VERSION 5.8 ;
BUSBITCHARS "[]" ;
DIVIDERCHAR "/" ;
UNITS
    DATABASE MICRONS 1000 ;
END UNITS

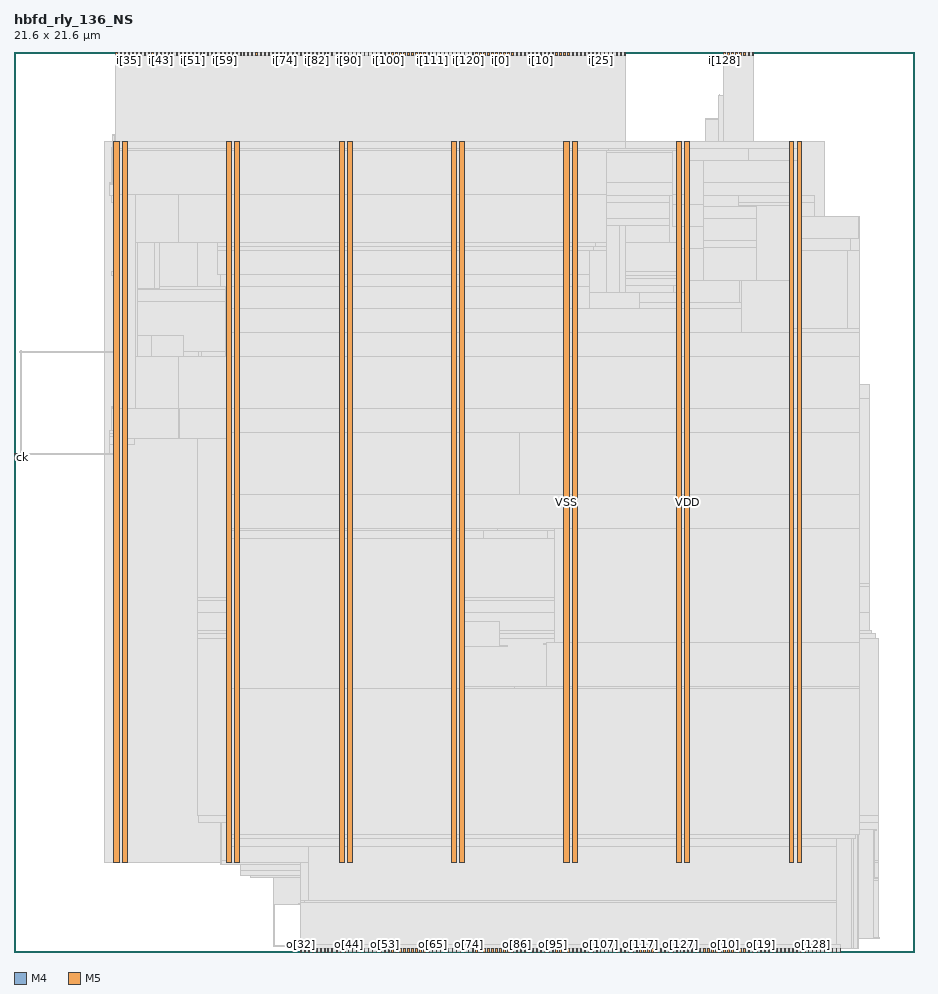
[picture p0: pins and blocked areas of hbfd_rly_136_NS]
MACRO hbfd_rly_136_NS
  FOREIGN hbfd_rly_136_NS 0 0 ;
  CLASS BLOCK ;
  SIZE 21.6 BY 21.6 ;
  PIN ck
    DIRECTION INPUT ;
    USE SIGNAL ;
    PORT
      LAYER M4 ;
        RECT  0 11.856 0.084 11.88 ;
    END
  END ck
  PIN i[0]
    DIRECTION INPUT ;
    USE SIGNAL ;
    PORT
      LAYER M5 ;
        RECT  11.664 21.516 11.688 21.6 ;
    END
  END i[0]
  PIN i[100]
    DIRECTION INPUT ;
    USE SIGNAL ;
    PORT
      LAYER M5 ;
        RECT  8.976 21.516 9 21.6 ;
    END
  END i[100]
  PIN i[101]
    DIRECTION INPUT ;
    USE SIGNAL ;
    PORT
      LAYER M5 ;
        RECT  9.072 21.516 9.096 21.6 ;
    END
  END i[101]
  PIN i[102]
    DIRECTION INPUT ;
    USE SIGNAL ;
    PORT
      LAYER M5 ;
        RECT  9.168 21.516 9.192 21.6 ;
    END
  END i[102]
  PIN i[103]
    DIRECTION INPUT ;
    USE SIGNAL ;
    PORT
      LAYER M5 ;
        RECT  9.264 21.516 9.288 21.6 ;
    END
  END i[103]
  PIN i[104]
    DIRECTION INPUT ;
    USE SIGNAL ;
    PORT
      LAYER M5 ;
        RECT  9.36 21.516 9.384 21.6 ;
    END
  END i[104]
  PIN i[105]
    DIRECTION INPUT ;
    USE SIGNAL ;
    PORT
      LAYER M5 ;
        RECT  9.456 21.516 9.48 21.6 ;
    END
  END i[105]
  PIN i[106]
    DIRECTION INPUT ;
    USE SIGNAL ;
    PORT
      LAYER M5 ;
        RECT  9.552 21.516 9.576 21.6 ;
    END
  END i[106]
  PIN i[107]
    DIRECTION INPUT ;
    USE SIGNAL ;
    PORT
      LAYER M5 ;
        RECT  9.648 21.516 9.672 21.6 ;
    END
  END i[107]
  PIN i[108]
    DIRECTION INPUT ;
    USE SIGNAL ;
    PORT
      LAYER M5 ;
        RECT  9.744 21.516 9.768 21.6 ;
    END
  END i[108]
  PIN i[109]
    DIRECTION INPUT ;
    USE SIGNAL ;
    PORT
      LAYER M5 ;
        RECT  9.84 21.516 9.864 21.6 ;
    END
  END i[109]
  PIN i[10]
    DIRECTION INPUT ;
    USE SIGNAL ;
    PORT
      LAYER M5 ;
        RECT  12.624 21.516 12.648 21.6 ;
    END
  END i[10]
  PIN i[110]
    DIRECTION INPUT ;
    USE SIGNAL ;
    PORT
      LAYER M5 ;
        RECT  9.936 21.516 9.96 21.6 ;
    END
  END i[110]
  PIN i[111]
    DIRECTION INPUT ;
    USE SIGNAL ;
    PORT
      LAYER M5 ;
        RECT  10.032 21.516 10.056 21.6 ;
    END
  END i[111]
  PIN i[112]
    DIRECTION INPUT ;
    USE SIGNAL ;
    PORT
      LAYER M5 ;
        RECT  10.128 21.516 10.152 21.6 ;
    END
  END i[112]
  PIN i[113]
    DIRECTION INPUT ;
    USE SIGNAL ;
    PORT
      LAYER M5 ;
        RECT  10.224 21.516 10.248 21.6 ;
    END
  END i[113]
  PIN i[114]
    DIRECTION INPUT ;
    USE SIGNAL ;
    PORT
      LAYER M5 ;
        RECT  10.32 21.516 10.344 21.6 ;
    END
  END i[114]
  PIN i[115]
    DIRECTION INPUT ;
    USE SIGNAL ;
    PORT
      LAYER M5 ;
        RECT  10.416 21.516 10.44 21.6 ;
    END
  END i[115]
  PIN i[116]
    DIRECTION INPUT ;
    USE SIGNAL ;
    PORT
      LAYER M5 ;
        RECT  10.512 21.516 10.536 21.6 ;
    END
  END i[116]
  PIN i[117]
    DIRECTION INPUT ;
    USE SIGNAL ;
    PORT
      LAYER M5 ;
        RECT  10.608 21.516 10.632 21.6 ;
    END
  END i[117]
  PIN i[118]
    DIRECTION INPUT ;
    USE SIGNAL ;
    PORT
      LAYER M5 ;
        RECT  10.704 21.516 10.728 21.6 ;
    END
  END i[118]
  PIN i[119]
    DIRECTION INPUT ;
    USE SIGNAL ;
    PORT
      LAYER M5 ;
        RECT  10.8 21.516 10.824 21.6 ;
    END
  END i[119]
  PIN i[11]
    DIRECTION INPUT ;
    USE SIGNAL ;
    PORT
      LAYER M5 ;
        RECT  12.72 21.516 12.744 21.6 ;
    END
  END i[11]
  PIN i[120]
    DIRECTION INPUT ;
    USE SIGNAL ;
    PORT
      LAYER M5 ;
        RECT  10.896 21.516 10.92 21.6 ;
    END
  END i[120]
  PIN i[121]
    DIRECTION INPUT ;
    USE SIGNAL ;
    PORT
      LAYER M5 ;
        RECT  10.992 21.516 11.016 21.6 ;
    END
  END i[121]
  PIN i[122]
    DIRECTION INPUT ;
    USE SIGNAL ;
    PORT
      LAYER M5 ;
        RECT  11.088 21.516 11.112 21.6 ;
    END
  END i[122]
  PIN i[123]
    DIRECTION INPUT ;
    USE SIGNAL ;
    PORT
      LAYER M5 ;
        RECT  11.184 21.516 11.208 21.6 ;
    END
  END i[123]
  PIN i[124]
    DIRECTION INPUT ;
    USE SIGNAL ;
    PORT
      LAYER M5 ;
        RECT  11.28 21.516 11.304 21.6 ;
    END
  END i[124]
  PIN i[125]
    DIRECTION INPUT ;
    USE SIGNAL ;
    PORT
      LAYER M5 ;
        RECT  11.376 21.516 11.4 21.6 ;
    END
  END i[125]
  PIN i[126]
    DIRECTION INPUT ;
    USE SIGNAL ;
    PORT
      LAYER M5 ;
        RECT  11.472 21.516 11.496 21.6 ;
    END
  END i[126]
  PIN i[127]
    DIRECTION INPUT ;
    USE SIGNAL ;
    PORT
      LAYER M5 ;
        RECT  11.568 21.516 11.592 21.6 ;
    END
  END i[127]
  PIN i[128]
    DIRECTION INPUT ;
    USE SIGNAL ;
    PORT
      LAYER M5 ;
        RECT  17.04 21.516 17.064 21.6 ;
    END
  END i[128]
  PIN i[129]
    DIRECTION INPUT ;
    USE SIGNAL ;
    PORT
      LAYER M5 ;
        RECT  17.136 21.516 17.16 21.6 ;
    END
  END i[129]
  PIN i[12]
    DIRECTION INPUT ;
    USE SIGNAL ;
    PORT
      LAYER M5 ;
        RECT  12.816 21.516 12.84 21.6 ;
    END
  END i[12]
  PIN i[130]
    DIRECTION INPUT ;
    USE SIGNAL ;
    PORT
      LAYER M5 ;
        RECT  17.232 21.516 17.256 21.6 ;
    END
  END i[130]
  PIN i[131]
    DIRECTION INPUT ;
    USE SIGNAL ;
    PORT
      LAYER M5 ;
        RECT  17.328 21.516 17.352 21.6 ;
    END
  END i[131]
  PIN i[132]
    DIRECTION INPUT ;
    USE SIGNAL ;
    PORT
      LAYER M5 ;
        RECT  17.424 21.516 17.448 21.6 ;
    END
  END i[132]
  PIN i[133]
    DIRECTION INPUT ;
    USE SIGNAL ;
    PORT
      LAYER M5 ;
        RECT  17.52 21.516 17.544 21.6 ;
    END
  END i[133]
  PIN i[134]
    DIRECTION INPUT ;
    USE SIGNAL ;
    PORT
      LAYER M5 ;
        RECT  17.616 21.516 17.64 21.6 ;
    END
  END i[134]
  PIN i[135]
    DIRECTION INPUT ;
    USE SIGNAL ;
    PORT
      LAYER M5 ;
        RECT  17.712 21.516 17.736 21.6 ;
    END
  END i[135]
  PIN i[13]
    DIRECTION INPUT ;
    USE SIGNAL ;
    PORT
      LAYER M5 ;
        RECT  12.912 21.516 12.936 21.6 ;
    END
  END i[13]
  PIN i[14]
    DIRECTION INPUT ;
    USE SIGNAL ;
    PORT
      LAYER M5 ;
        RECT  13.008 21.516 13.032 21.6 ;
    END
  END i[14]
  PIN i[15]
    DIRECTION INPUT ;
    USE SIGNAL ;
    PORT
      LAYER M5 ;
        RECT  13.104 21.516 13.128 21.6 ;
    END
  END i[15]
  PIN i[16]
    DIRECTION INPUT ;
    USE SIGNAL ;
    PORT
      LAYER M5 ;
        RECT  13.2 21.516 13.224 21.6 ;
    END
  END i[16]
  PIN i[17]
    DIRECTION INPUT ;
    USE SIGNAL ;
    PORT
      LAYER M5 ;
        RECT  13.296 21.516 13.32 21.6 ;
    END
  END i[17]
  PIN i[18]
    DIRECTION INPUT ;
    USE SIGNAL ;
    PORT
      LAYER M5 ;
        RECT  13.392 21.516 13.416 21.6 ;
    END
  END i[18]
  PIN i[19]
    DIRECTION INPUT ;
    USE SIGNAL ;
    PORT
      LAYER M5 ;
        RECT  13.488 21.516 13.512 21.6 ;
    END
  END i[19]
  PIN i[1]
    DIRECTION INPUT ;
    USE SIGNAL ;
    PORT
      LAYER M5 ;
        RECT  11.76 21.516 11.784 21.6 ;
    END
  END i[1]
  PIN i[20]
    DIRECTION INPUT ;
    USE SIGNAL ;
    PORT
      LAYER M5 ;
        RECT  13.584 21.516 13.608 21.6 ;
    END
  END i[20]
  PIN i[21]
    DIRECTION INPUT ;
    USE SIGNAL ;
    PORT
      LAYER M5 ;
        RECT  13.68 21.516 13.704 21.6 ;
    END
  END i[21]
  PIN i[22]
    DIRECTION INPUT ;
    USE SIGNAL ;
    PORT
      LAYER M5 ;
        RECT  13.776 21.516 13.8 21.6 ;
    END
  END i[22]
  PIN i[23]
    DIRECTION INPUT ;
    USE SIGNAL ;
    PORT
      LAYER M5 ;
        RECT  13.872 21.516 13.896 21.6 ;
    END
  END i[23]
  PIN i[24]
    DIRECTION INPUT ;
    USE SIGNAL ;
    PORT
      LAYER M5 ;
        RECT  13.968 21.516 13.992 21.6 ;
    END
  END i[24]
  PIN i[25]
    DIRECTION INPUT ;
    USE SIGNAL ;
    PORT
      LAYER M5 ;
        RECT  14.064 21.516 14.088 21.6 ;
    END
  END i[25]
  PIN i[26]
    DIRECTION INPUT ;
    USE SIGNAL ;
    PORT
      LAYER M5 ;
        RECT  14.16 21.516 14.184 21.6 ;
    END
  END i[26]
  PIN i[27]
    DIRECTION INPUT ;
    USE SIGNAL ;
    PORT
      LAYER M5 ;
        RECT  14.256 21.516 14.28 21.6 ;
    END
  END i[27]
  PIN i[28]
    DIRECTION INPUT ;
    USE SIGNAL ;
    PORT
      LAYER M5 ;
        RECT  14.352 21.516 14.376 21.6 ;
    END
  END i[28]
  PIN i[29]
    DIRECTION INPUT ;
    USE SIGNAL ;
    PORT
      LAYER M5 ;
        RECT  14.448 21.516 14.472 21.6 ;
    END
  END i[29]
  PIN i[2]
    DIRECTION INPUT ;
    USE SIGNAL ;
    PORT
      LAYER M5 ;
        RECT  11.856 21.516 11.88 21.6 ;
    END
  END i[2]
  PIN i[30]
    DIRECTION INPUT ;
    USE SIGNAL ;
    PORT
      LAYER M5 ;
        RECT  14.544 21.516 14.568 21.6 ;
    END
  END i[30]
  PIN i[31]
    DIRECTION INPUT ;
    USE SIGNAL ;
    PORT
      LAYER M5 ;
        RECT  14.64 21.516 14.664 21.6 ;
    END
  END i[31]
  PIN i[32]
    DIRECTION INPUT ;
    USE SIGNAL ;
    PORT
      LAYER M5 ;
        RECT  2.448 21.516 2.472 21.6 ;
    END
  END i[32]
  PIN i[33]
    DIRECTION INPUT ;
    USE SIGNAL ;
    PORT
      LAYER M5 ;
        RECT  2.544 21.516 2.568 21.6 ;
    END
  END i[33]
  PIN i[34]
    DIRECTION INPUT ;
    USE SIGNAL ;
    PORT
      LAYER M5 ;
        RECT  2.64 21.516 2.664 21.6 ;
    END
  END i[34]
  PIN i[35]
    DIRECTION INPUT ;
    USE SIGNAL ;
    PORT
      LAYER M5 ;
        RECT  2.736 21.516 2.76 21.6 ;
    END
  END i[35]
  PIN i[36]
    DIRECTION INPUT ;
    USE SIGNAL ;
    PORT
      LAYER M5 ;
        RECT  2.832 21.516 2.856 21.6 ;
    END
  END i[36]
  PIN i[37]
    DIRECTION INPUT ;
    USE SIGNAL ;
    PORT
      LAYER M5 ;
        RECT  2.928 21.516 2.952 21.6 ;
    END
  END i[37]
  PIN i[38]
    DIRECTION INPUT ;
    USE SIGNAL ;
    PORT
      LAYER M5 ;
        RECT  3.024 21.516 3.048 21.6 ;
    END
  END i[38]
  PIN i[39]
    DIRECTION INPUT ;
    USE SIGNAL ;
    PORT
      LAYER M5 ;
        RECT  3.12 21.516 3.144 21.6 ;
    END
  END i[39]
  PIN i[3]
    DIRECTION INPUT ;
    USE SIGNAL ;
    PORT
      LAYER M5 ;
        RECT  11.952 21.516 11.976 21.6 ;
    END
  END i[3]
  PIN i[40]
    DIRECTION INPUT ;
    USE SIGNAL ;
    PORT
      LAYER M5 ;
        RECT  3.216 21.516 3.24 21.6 ;
    END
  END i[40]
  PIN i[41]
    DIRECTION INPUT ;
    USE SIGNAL ;
    PORT
      LAYER M5 ;
        RECT  3.312 21.516 3.336 21.6 ;
    END
  END i[41]
  PIN i[42]
    DIRECTION INPUT ;
    USE SIGNAL ;
    PORT
      LAYER M5 ;
        RECT  3.408 21.516 3.432 21.6 ;
    END
  END i[42]
  PIN i[43]
    DIRECTION INPUT ;
    USE SIGNAL ;
    PORT
      LAYER M5 ;
        RECT  3.504 21.516 3.528 21.6 ;
    END
  END i[43]
  PIN i[44]
    DIRECTION INPUT ;
    USE SIGNAL ;
    PORT
      LAYER M5 ;
        RECT  3.6 21.516 3.624 21.6 ;
    END
  END i[44]
  PIN i[45]
    DIRECTION INPUT ;
    USE SIGNAL ;
    PORT
      LAYER M5 ;
        RECT  3.696 21.516 3.72 21.6 ;
    END
  END i[45]
  PIN i[46]
    DIRECTION INPUT ;
    USE SIGNAL ;
    PORT
      LAYER M5 ;
        RECT  3.792 21.516 3.816 21.6 ;
    END
  END i[46]
  PIN i[47]
    DIRECTION INPUT ;
    USE SIGNAL ;
    PORT
      LAYER M5 ;
        RECT  3.888 21.516 3.912 21.6 ;
    END
  END i[47]
  PIN i[48]
    DIRECTION INPUT ;
    USE SIGNAL ;
    PORT
      LAYER M5 ;
        RECT  3.984 21.516 4.008 21.6 ;
    END
  END i[48]
  PIN i[49]
    DIRECTION INPUT ;
    USE SIGNAL ;
    PORT
      LAYER M5 ;
        RECT  4.08 21.516 4.104 21.6 ;
    END
  END i[49]
  PIN i[4]
    DIRECTION INPUT ;
    USE SIGNAL ;
    PORT
      LAYER M5 ;
        RECT  12.048 21.516 12.072 21.6 ;
    END
  END i[4]
  PIN i[50]
    DIRECTION INPUT ;
    USE SIGNAL ;
    PORT
      LAYER M5 ;
        RECT  4.176 21.516 4.2 21.6 ;
    END
  END i[50]
  PIN i[51]
    DIRECTION INPUT ;
    USE SIGNAL ;
    PORT
      LAYER M5 ;
        RECT  4.272 21.516 4.296 21.6 ;
    END
  END i[51]
  PIN i[52]
    DIRECTION INPUT ;
    USE SIGNAL ;
    PORT
      LAYER M5 ;
        RECT  4.368 21.516 4.392 21.6 ;
    END
  END i[52]
  PIN i[53]
    DIRECTION INPUT ;
    USE SIGNAL ;
    PORT
      LAYER M5 ;
        RECT  4.464 21.516 4.488 21.6 ;
    END
  END i[53]
  PIN i[54]
    DIRECTION INPUT ;
    USE SIGNAL ;
    PORT
      LAYER M5 ;
        RECT  4.56 21.516 4.584 21.6 ;
    END
  END i[54]
  PIN i[55]
    DIRECTION INPUT ;
    USE SIGNAL ;
    PORT
      LAYER M5 ;
        RECT  4.656 21.516 4.68 21.6 ;
    END
  END i[55]
  PIN i[56]
    DIRECTION INPUT ;
    USE SIGNAL ;
    PORT
      LAYER M5 ;
        RECT  4.752 21.516 4.776 21.6 ;
    END
  END i[56]
  PIN i[57]
    DIRECTION INPUT ;
    USE SIGNAL ;
    PORT
      LAYER M5 ;
        RECT  4.848 21.516 4.872 21.6 ;
    END
  END i[57]
  PIN i[58]
    DIRECTION INPUT ;
    USE SIGNAL ;
    PORT
      LAYER M5 ;
        RECT  4.944 21.516 4.968 21.6 ;
    END
  END i[58]
  PIN i[59]
    DIRECTION INPUT ;
    USE SIGNAL ;
    PORT
      LAYER M5 ;
        RECT  5.04 21.516 5.064 21.6 ;
    END
  END i[59]
  PIN i[5]
    DIRECTION INPUT ;
    USE SIGNAL ;
    PORT
      LAYER M5 ;
        RECT  12.144 21.516 12.168 21.6 ;
    END
  END i[5]
  PIN i[60]
    DIRECTION INPUT ;
    USE SIGNAL ;
    PORT
      LAYER M5 ;
        RECT  5.136 21.516 5.16 21.6 ;
    END
  END i[60]
  PIN i[61]
    DIRECTION INPUT ;
    USE SIGNAL ;
    PORT
      LAYER M5 ;
        RECT  5.232 21.516 5.256 21.6 ;
    END
  END i[61]
  PIN i[62]
    DIRECTION INPUT ;
    USE SIGNAL ;
    PORT
      LAYER M5 ;
        RECT  5.328 21.516 5.352 21.6 ;
    END
  END i[62]
  PIN i[63]
    DIRECTION INPUT ;
    USE SIGNAL ;
    PORT
      LAYER M5 ;
        RECT  5.424 21.516 5.448 21.6 ;
    END
  END i[63]
  PIN i[64]
    DIRECTION INPUT ;
    USE SIGNAL ;
    PORT
      LAYER M5 ;
        RECT  5.52 21.516 5.544 21.6 ;
    END
  END i[64]
  PIN i[65]
    DIRECTION INPUT ;
    USE SIGNAL ;
    PORT
      LAYER M5 ;
        RECT  5.616 21.516 5.64 21.6 ;
    END
  END i[65]
  PIN i[66]
    DIRECTION INPUT ;
    USE SIGNAL ;
    PORT
      LAYER M5 ;
        RECT  5.712 21.516 5.736 21.6 ;
    END
  END i[66]
  PIN i[67]
    DIRECTION INPUT ;
    USE SIGNAL ;
    PORT
      LAYER M5 ;
        RECT  5.808 21.516 5.832 21.6 ;
    END
  END i[67]
  PIN i[68]
    DIRECTION INPUT ;
    USE SIGNAL ;
    PORT
      LAYER M5 ;
        RECT  5.904 21.516 5.928 21.6 ;
    END
  END i[68]
  PIN i[69]
    DIRECTION INPUT ;
    USE SIGNAL ;
    PORT
      LAYER M5 ;
        RECT  6 21.516 6.024 21.6 ;
    END
  END i[69]
  PIN i[6]
    DIRECTION INPUT ;
    USE SIGNAL ;
    PORT
      LAYER M5 ;
        RECT  12.24 21.516 12.264 21.6 ;
    END
  END i[6]
  PIN i[70]
    DIRECTION INPUT ;
    USE SIGNAL ;
    PORT
      LAYER M5 ;
        RECT  6.096 21.516 6.12 21.6 ;
    END
  END i[70]
  PIN i[71]
    DIRECTION INPUT ;
    USE SIGNAL ;
    PORT
      LAYER M5 ;
        RECT  6.192 21.516 6.216 21.6 ;
    END
  END i[71]
  PIN i[72]
    DIRECTION INPUT ;
    USE SIGNAL ;
    PORT
      LAYER M5 ;
        RECT  6.288 21.516 6.312 21.6 ;
    END
  END i[72]
  PIN i[73]
    DIRECTION INPUT ;
    USE SIGNAL ;
    PORT
      LAYER M5 ;
        RECT  6.384 21.516 6.408 21.6 ;
    END
  END i[73]
  PIN i[74]
    DIRECTION INPUT ;
    USE SIGNAL ;
    PORT
      LAYER M5 ;
        RECT  6.48 21.516 6.504 21.6 ;
    END
  END i[74]
  PIN i[75]
    DIRECTION INPUT ;
    USE SIGNAL ;
    PORT
      LAYER M5 ;
        RECT  6.576 21.516 6.6 21.6 ;
    END
  END i[75]
  PIN i[76]
    DIRECTION INPUT ;
    USE SIGNAL ;
    PORT
      LAYER M5 ;
        RECT  6.672 21.516 6.696 21.6 ;
    END
  END i[76]
  PIN i[77]
    DIRECTION INPUT ;
    USE SIGNAL ;
    PORT
      LAYER M5 ;
        RECT  6.768 21.516 6.792 21.6 ;
    END
  END i[77]
  PIN i[78]
    DIRECTION INPUT ;
    USE SIGNAL ;
    PORT
      LAYER M5 ;
        RECT  6.864 21.516 6.888 21.6 ;
    END
  END i[78]
  PIN i[79]
    DIRECTION INPUT ;
    USE SIGNAL ;
    PORT
      LAYER M5 ;
        RECT  6.96 21.516 6.984 21.6 ;
    END
  END i[79]
  PIN i[7]
    DIRECTION INPUT ;
    USE SIGNAL ;
    PORT
      LAYER M5 ;
        RECT  12.336 21.516 12.36 21.6 ;
    END
  END i[7]
  PIN i[80]
    DIRECTION INPUT ;
    USE SIGNAL ;
    PORT
      LAYER M5 ;
        RECT  7.056 21.516 7.08 21.6 ;
    END
  END i[80]
  PIN i[81]
    DIRECTION INPUT ;
    USE SIGNAL ;
    PORT
      LAYER M5 ;
        RECT  7.152 21.516 7.176 21.6 ;
    END
  END i[81]
  PIN i[82]
    DIRECTION INPUT ;
    USE SIGNAL ;
    PORT
      LAYER M5 ;
        RECT  7.248 21.516 7.272 21.6 ;
    END
  END i[82]
  PIN i[83]
    DIRECTION INPUT ;
    USE SIGNAL ;
    PORT
      LAYER M5 ;
        RECT  7.344 21.516 7.368 21.6 ;
    END
  END i[83]
  PIN i[84]
    DIRECTION INPUT ;
    USE SIGNAL ;
    PORT
      LAYER M5 ;
        RECT  7.44 21.516 7.464 21.6 ;
    END
  END i[84]
  PIN i[85]
    DIRECTION INPUT ;
    USE SIGNAL ;
    PORT
      LAYER M5 ;
        RECT  7.536 21.516 7.56 21.6 ;
    END
  END i[85]
  PIN i[86]
    DIRECTION INPUT ;
    USE SIGNAL ;
    PORT
      LAYER M5 ;
        RECT  7.632 21.516 7.656 21.6 ;
    END
  END i[86]
  PIN i[87]
    DIRECTION INPUT ;
    USE SIGNAL ;
    PORT
      LAYER M5 ;
        RECT  7.728 21.516 7.752 21.6 ;
    END
  END i[87]
  PIN i[88]
    DIRECTION INPUT ;
    USE SIGNAL ;
    PORT
      LAYER M5 ;
        RECT  7.824 21.516 7.848 21.6 ;
    END
  END i[88]
  PIN i[89]
    DIRECTION INPUT ;
    USE SIGNAL ;
    PORT
      LAYER M5 ;
        RECT  7.92 21.516 7.944 21.6 ;
    END
  END i[89]
  PIN i[8]
    DIRECTION INPUT ;
    USE SIGNAL ;
    PORT
      LAYER M5 ;
        RECT  12.432 21.516 12.456 21.6 ;
    END
  END i[8]
  PIN i[90]
    DIRECTION INPUT ;
    USE SIGNAL ;
    PORT
      LAYER M5 ;
        RECT  8.016 21.516 8.04 21.6 ;
    END
  END i[90]
  PIN i[91]
    DIRECTION INPUT ;
    USE SIGNAL ;
    PORT
      LAYER M5 ;
        RECT  8.112 21.516 8.136 21.6 ;
    END
  END i[91]
  PIN i[92]
    DIRECTION INPUT ;
    USE SIGNAL ;
    PORT
      LAYER M5 ;
        RECT  8.208 21.516 8.232 21.6 ;
    END
  END i[92]
  PIN i[93]
    DIRECTION INPUT ;
    USE SIGNAL ;
    PORT
      LAYER M5 ;
        RECT  8.304 21.516 8.328 21.6 ;
    END
  END i[93]
  PIN i[94]
    DIRECTION INPUT ;
    USE SIGNAL ;
    PORT
      LAYER M5 ;
        RECT  8.4 21.516 8.424 21.6 ;
    END
  END i[94]
  PIN i[95]
    DIRECTION INPUT ;
    USE SIGNAL ;
    PORT
      LAYER M5 ;
        RECT  8.496 21.516 8.52 21.6 ;
    END
  END i[95]
  PIN i[96]
    DIRECTION INPUT ;
    USE SIGNAL ;
    PORT
      LAYER M5 ;
        RECT  8.592 21.516 8.616 21.6 ;
    END
  END i[96]
  PIN i[97]
    DIRECTION INPUT ;
    USE SIGNAL ;
    PORT
      LAYER M5 ;
        RECT  8.688 21.516 8.712 21.6 ;
    END
  END i[97]
  PIN i[98]
    DIRECTION INPUT ;
    USE SIGNAL ;
    PORT
      LAYER M5 ;
        RECT  8.784 21.516 8.808 21.6 ;
    END
  END i[98]
  PIN i[99]
    DIRECTION INPUT ;
    USE SIGNAL ;
    PORT
      LAYER M5 ;
        RECT  8.88 21.516 8.904 21.6 ;
    END
  END i[99]
  PIN i[9]
    DIRECTION INPUT ;
    USE SIGNAL ;
    PORT
      LAYER M5 ;
        RECT  12.528 21.516 12.552 21.6 ;
    END
  END i[9]
  PIN o[0]
    DIRECTION OUTPUT ;
    USE SIGNAL ;
    PORT
      LAYER M5 ;
        RECT  16.08 0 16.104 0.084 ;
    END
  END o[0]
  PIN o[100]
    DIRECTION OUTPUT ;
    USE SIGNAL ;
    PORT
      LAYER M5 ;
        RECT  13.392 0 13.416 0.084 ;
    END
  END o[100]
  PIN o[101]
    DIRECTION OUTPUT ;
    USE SIGNAL ;
    PORT
      LAYER M5 ;
        RECT  13.488 0 13.512 0.084 ;
    END
  END o[101]
  PIN o[102]
    DIRECTION OUTPUT ;
    USE SIGNAL ;
    PORT
      LAYER M5 ;
        RECT  13.584 0 13.608 0.084 ;
    END
  END o[102]
  PIN o[103]
    DIRECTION OUTPUT ;
    USE SIGNAL ;
    PORT
      LAYER M5 ;
        RECT  13.68 0 13.704 0.084 ;
    END
  END o[103]
  PIN o[104]
    DIRECTION OUTPUT ;
    USE SIGNAL ;
    PORT
      LAYER M5 ;
        RECT  13.776 0 13.8 0.084 ;
    END
  END o[104]
  PIN o[105]
    DIRECTION OUTPUT ;
    USE SIGNAL ;
    PORT
      LAYER M5 ;
        RECT  13.872 0 13.896 0.084 ;
    END
  END o[105]
  PIN o[106]
    DIRECTION OUTPUT ;
    USE SIGNAL ;
    PORT
      LAYER M5 ;
        RECT  13.968 0 13.992 0.084 ;
    END
  END o[106]
  PIN o[107]
    DIRECTION OUTPUT ;
    USE SIGNAL ;
    PORT
      LAYER M5 ;
        RECT  14.064 0 14.088 0.084 ;
    END
  END o[107]
  PIN o[108]
    DIRECTION OUTPUT ;
    USE SIGNAL ;
    PORT
      LAYER M5 ;
        RECT  14.16 0 14.184 0.084 ;
    END
  END o[108]
  PIN o[109]
    DIRECTION OUTPUT ;
    USE SIGNAL ;
    PORT
      LAYER M5 ;
        RECT  14.256 0 14.28 0.084 ;
    END
  END o[109]
  PIN o[10]
    DIRECTION OUTPUT ;
    USE SIGNAL ;
    PORT
      LAYER M5 ;
        RECT  17.04 0 17.064 0.084 ;
    END
  END o[10]
  PIN o[110]
    DIRECTION OUTPUT ;
    USE SIGNAL ;
    PORT
      LAYER M5 ;
        RECT  14.352 0 14.376 0.084 ;
    END
  END o[110]
  PIN o[111]
    DIRECTION OUTPUT ;
    USE SIGNAL ;
    PORT
      LAYER M5 ;
        RECT  14.448 0 14.472 0.084 ;
    END
  END o[111]
  PIN o[112]
    DIRECTION OUTPUT ;
    USE SIGNAL ;
    PORT
      LAYER M5 ;
        RECT  14.544 0 14.568 0.084 ;
    END
  END o[112]
  PIN o[113]
    DIRECTION OUTPUT ;
    USE SIGNAL ;
    PORT
      LAYER M5 ;
        RECT  14.64 0 14.664 0.084 ;
    END
  END o[113]
  PIN o[114]
    DIRECTION OUTPUT ;
    USE SIGNAL ;
    PORT
      LAYER M5 ;
        RECT  14.736 0 14.76 0.084 ;
    END
  END o[114]
  PIN o[115]
    DIRECTION OUTPUT ;
    USE SIGNAL ;
    PORT
      LAYER M5 ;
        RECT  14.832 0 14.856 0.084 ;
    END
  END o[115]
  PIN o[116]
    DIRECTION OUTPUT ;
    USE SIGNAL ;
    PORT
      LAYER M5 ;
        RECT  14.928 0 14.952 0.084 ;
    END
  END o[116]
  PIN o[117]
    DIRECTION OUTPUT ;
    USE SIGNAL ;
    PORT
      LAYER M5 ;
        RECT  15.024 0 15.048 0.084 ;
    END
  END o[117]
  PIN o[118]
    DIRECTION OUTPUT ;
    USE SIGNAL ;
    PORT
      LAYER M5 ;
        RECT  15.12 0 15.144 0.084 ;
    END
  END o[118]
  PIN o[119]
    DIRECTION OUTPUT ;
    USE SIGNAL ;
    PORT
      LAYER M5 ;
        RECT  15.216 0 15.24 0.084 ;
    END
  END o[119]
  PIN o[11]
    DIRECTION OUTPUT ;
    USE SIGNAL ;
    PORT
      LAYER M5 ;
        RECT  17.136 0 17.16 0.084 ;
    END
  END o[11]
  PIN o[120]
    DIRECTION OUTPUT ;
    USE SIGNAL ;
    PORT
      LAYER M5 ;
        RECT  15.312 0 15.336 0.084 ;
    END
  END o[120]
  PIN o[121]
    DIRECTION OUTPUT ;
    USE SIGNAL ;
    PORT
      LAYER M5 ;
        RECT  15.408 0 15.432 0.084 ;
    END
  END o[121]
  PIN o[122]
    DIRECTION OUTPUT ;
    USE SIGNAL ;
    PORT
      LAYER M5 ;
        RECT  15.504 0 15.528 0.084 ;
    END
  END o[122]
  PIN o[123]
    DIRECTION OUTPUT ;
    USE SIGNAL ;
    PORT
      LAYER M5 ;
        RECT  15.6 0 15.624 0.084 ;
    END
  END o[123]
  PIN o[124]
    DIRECTION OUTPUT ;
    USE SIGNAL ;
    PORT
      LAYER M5 ;
        RECT  15.696 0 15.72 0.084 ;
    END
  END o[124]
  PIN o[125]
    DIRECTION OUTPUT ;
    USE SIGNAL ;
    PORT
      LAYER M5 ;
        RECT  15.792 0 15.816 0.084 ;
    END
  END o[125]
  PIN o[126]
    DIRECTION OUTPUT ;
    USE SIGNAL ;
    PORT
      LAYER M5 ;
        RECT  15.888 0 15.912 0.084 ;
    END
  END o[126]
  PIN o[127]
    DIRECTION OUTPUT ;
    USE SIGNAL ;
    PORT
      LAYER M5 ;
        RECT  15.984 0 16.008 0.084 ;
    END
  END o[127]
  PIN o[128]
    DIRECTION OUTPUT ;
    USE SIGNAL ;
    PORT
      LAYER M5 ;
        RECT  19.152 0 19.176 0.084 ;
    END
  END o[128]
  PIN o[129]
    DIRECTION OUTPUT ;
    USE SIGNAL ;
    PORT
      LAYER M5 ;
        RECT  19.248 0 19.272 0.084 ;
    END
  END o[129]
  PIN o[12]
    DIRECTION OUTPUT ;
    USE SIGNAL ;
    PORT
      LAYER M5 ;
        RECT  17.232 0 17.256 0.084 ;
    END
  END o[12]
  PIN o[130]
    DIRECTION OUTPUT ;
    USE SIGNAL ;
    PORT
      LAYER M5 ;
        RECT  19.344 0 19.368 0.084 ;
    END
  END o[130]
  PIN o[131]
    DIRECTION OUTPUT ;
    USE SIGNAL ;
    PORT
      LAYER M5 ;
        RECT  19.44 0 19.464 0.084 ;
    END
  END o[131]
  PIN o[132]
    DIRECTION OUTPUT ;
    USE SIGNAL ;
    PORT
      LAYER M5 ;
        RECT  19.536 0 19.56 0.084 ;
    END
  END o[132]
  PIN o[133]
    DIRECTION OUTPUT ;
    USE SIGNAL ;
    PORT
      LAYER M5 ;
        RECT  19.632 0 19.656 0.084 ;
    END
  END o[133]
  PIN o[134]
    DIRECTION OUTPUT ;
    USE SIGNAL ;
    PORT
      LAYER M5 ;
        RECT  19.728 0 19.752 0.084 ;
    END
  END o[134]
  PIN o[135]
    DIRECTION OUTPUT ;
    USE SIGNAL ;
    PORT
      LAYER M5 ;
        RECT  19.824 0 19.848 0.084 ;
    END
  END o[135]
  PIN o[13]
    DIRECTION OUTPUT ;
    USE SIGNAL ;
    PORT
      LAYER M5 ;
        RECT  17.328 0 17.352 0.084 ;
    END
  END o[13]
  PIN o[14]
    DIRECTION OUTPUT ;
    USE SIGNAL ;
    PORT
      LAYER M5 ;
        RECT  17.424 0 17.448 0.084 ;
    END
  END o[14]
  PIN o[15]
    DIRECTION OUTPUT ;
    USE SIGNAL ;
    PORT
      LAYER M5 ;
        RECT  17.52 0 17.544 0.084 ;
    END
  END o[15]
  PIN o[16]
    DIRECTION OUTPUT ;
    USE SIGNAL ;
    PORT
      LAYER M5 ;
        RECT  17.616 0 17.64 0.084 ;
    END
  END o[16]
  PIN o[17]
    DIRECTION OUTPUT ;
    USE SIGNAL ;
    PORT
      LAYER M5 ;
        RECT  17.712 0 17.736 0.084 ;
    END
  END o[17]
  PIN o[18]
    DIRECTION OUTPUT ;
    USE SIGNAL ;
    PORT
      LAYER M5 ;
        RECT  17.808 0 17.832 0.084 ;
    END
  END o[18]
  PIN o[19]
    DIRECTION OUTPUT ;
    USE SIGNAL ;
    PORT
      LAYER M5 ;
        RECT  17.904 0 17.928 0.084 ;
    END
  END o[19]
  PIN o[1]
    DIRECTION OUTPUT ;
    USE SIGNAL ;
    PORT
      LAYER M5 ;
        RECT  16.176 0 16.2 0.084 ;
    END
  END o[1]
  PIN o[20]
    DIRECTION OUTPUT ;
    USE SIGNAL ;
    PORT
      LAYER M5 ;
        RECT  18 0 18.024 0.084 ;
    END
  END o[20]
  PIN o[21]
    DIRECTION OUTPUT ;
    USE SIGNAL ;
    PORT
      LAYER M5 ;
        RECT  18.096 0 18.12 0.084 ;
    END
  END o[21]
  PIN o[22]
    DIRECTION OUTPUT ;
    USE SIGNAL ;
    PORT
      LAYER M5 ;
        RECT  18.192 0 18.216 0.084 ;
    END
  END o[22]
  PIN o[23]
    DIRECTION OUTPUT ;
    USE SIGNAL ;
    PORT
      LAYER M5 ;
        RECT  18.288 0 18.312 0.084 ;
    END
  END o[23]
  PIN o[24]
    DIRECTION OUTPUT ;
    USE SIGNAL ;
    PORT
      LAYER M5 ;
        RECT  18.384 0 18.408 0.084 ;
    END
  END o[24]
  PIN o[25]
    DIRECTION OUTPUT ;
    USE SIGNAL ;
    PORT
      LAYER M5 ;
        RECT  18.48 0 18.504 0.084 ;
    END
  END o[25]
  PIN o[26]
    DIRECTION OUTPUT ;
    USE SIGNAL ;
    PORT
      LAYER M5 ;
        RECT  18.576 0 18.6 0.084 ;
    END
  END o[26]
  PIN o[27]
    DIRECTION OUTPUT ;
    USE SIGNAL ;
    PORT
      LAYER M5 ;
        RECT  18.672 0 18.696 0.084 ;
    END
  END o[27]
  PIN o[28]
    DIRECTION OUTPUT ;
    USE SIGNAL ;
    PORT
      LAYER M5 ;
        RECT  18.768 0 18.792 0.084 ;
    END
  END o[28]
  PIN o[29]
    DIRECTION OUTPUT ;
    USE SIGNAL ;
    PORT
      LAYER M5 ;
        RECT  18.864 0 18.888 0.084 ;
    END
  END o[29]
  PIN o[2]
    DIRECTION OUTPUT ;
    USE SIGNAL ;
    PORT
      LAYER M5 ;
        RECT  16.272 0 16.296 0.084 ;
    END
  END o[2]
  PIN o[30]
    DIRECTION OUTPUT ;
    USE SIGNAL ;
    PORT
      LAYER M5 ;
        RECT  18.96 0 18.984 0.084 ;
    END
  END o[30]
  PIN o[31]
    DIRECTION OUTPUT ;
    USE SIGNAL ;
    PORT
      LAYER M5 ;
        RECT  19.056 0 19.08 0.084 ;
    END
  END o[31]
  PIN o[32]
    DIRECTION OUTPUT ;
    USE SIGNAL ;
    PORT
      LAYER M5 ;
        RECT  6.864 0 6.888 0.084 ;
    END
  END o[32]
  PIN o[33]
    DIRECTION OUTPUT ;
    USE SIGNAL ;
    PORT
      LAYER M5 ;
        RECT  6.96 0 6.984 0.084 ;
    END
  END o[33]
  PIN o[34]
    DIRECTION OUTPUT ;
    USE SIGNAL ;
    PORT
      LAYER M5 ;
        RECT  7.056 0 7.08 0.084 ;
    END
  END o[34]
  PIN o[35]
    DIRECTION OUTPUT ;
    USE SIGNAL ;
    PORT
      LAYER M5 ;
        RECT  7.152 0 7.176 0.084 ;
    END
  END o[35]
  PIN o[36]
    DIRECTION OUTPUT ;
    USE SIGNAL ;
    PORT
      LAYER M5 ;
        RECT  7.248 0 7.272 0.084 ;
    END
  END o[36]
  PIN o[37]
    DIRECTION OUTPUT ;
    USE SIGNAL ;
    PORT
      LAYER M5 ;
        RECT  7.344 0 7.368 0.084 ;
    END
  END o[37]
  PIN o[38]
    DIRECTION OUTPUT ;
    USE SIGNAL ;
    PORT
      LAYER M5 ;
        RECT  7.44 0 7.464 0.084 ;
    END
  END o[38]
  PIN o[39]
    DIRECTION OUTPUT ;
    USE SIGNAL ;
    PORT
      LAYER M5 ;
        RECT  7.536 0 7.56 0.084 ;
    END
  END o[39]
  PIN o[3]
    DIRECTION OUTPUT ;
    USE SIGNAL ;
    PORT
      LAYER M5 ;
        RECT  16.368 0 16.392 0.084 ;
    END
  END o[3]
  PIN o[40]
    DIRECTION OUTPUT ;
    USE SIGNAL ;
    PORT
      LAYER M5 ;
        RECT  7.632 0 7.656 0.084 ;
    END
  END o[40]
  PIN o[41]
    DIRECTION OUTPUT ;
    USE SIGNAL ;
    PORT
      LAYER M5 ;
        RECT  7.728 0 7.752 0.084 ;
    END
  END o[41]
  PIN o[42]
    DIRECTION OUTPUT ;
    USE SIGNAL ;
    PORT
      LAYER M5 ;
        RECT  7.824 0 7.848 0.084 ;
    END
  END o[42]
  PIN o[43]
    DIRECTION OUTPUT ;
    USE SIGNAL ;
    PORT
      LAYER M5 ;
        RECT  7.92 0 7.944 0.084 ;
    END
  END o[43]
  PIN o[44]
    DIRECTION OUTPUT ;
    USE SIGNAL ;
    PORT
      LAYER M5 ;
        RECT  8.016 0 8.04 0.084 ;
    END
  END o[44]
  PIN o[45]
    DIRECTION OUTPUT ;
    USE SIGNAL ;
    PORT
      LAYER M5 ;
        RECT  8.112 0 8.136 0.084 ;
    END
  END o[45]
  PIN o[46]
    DIRECTION OUTPUT ;
    USE SIGNAL ;
    PORT
      LAYER M5 ;
        RECT  8.208 0 8.232 0.084 ;
    END
  END o[46]
  PIN o[47]
    DIRECTION OUTPUT ;
    USE SIGNAL ;
    PORT
      LAYER M5 ;
        RECT  8.304 0 8.328 0.084 ;
    END
  END o[47]
  PIN o[48]
    DIRECTION OUTPUT ;
    USE SIGNAL ;
    PORT
      LAYER M5 ;
        RECT  8.4 0 8.424 0.084 ;
    END
  END o[48]
  PIN o[49]
    DIRECTION OUTPUT ;
    USE SIGNAL ;
    PORT
      LAYER M5 ;
        RECT  8.496 0 8.52 0.084 ;
    END
  END o[49]
  PIN o[4]
    DIRECTION OUTPUT ;
    USE SIGNAL ;
    PORT
      LAYER M5 ;
        RECT  16.464 0 16.488 0.084 ;
    END
  END o[4]
  PIN o[50]
    DIRECTION OUTPUT ;
    USE SIGNAL ;
    PORT
      LAYER M5 ;
        RECT  8.592 0 8.616 0.084 ;
    END
  END o[50]
  PIN o[51]
    DIRECTION OUTPUT ;
    USE SIGNAL ;
    PORT
      LAYER M5 ;
        RECT  8.688 0 8.712 0.084 ;
    END
  END o[51]
  PIN o[52]
    DIRECTION OUTPUT ;
    USE SIGNAL ;
    PORT
      LAYER M5 ;
        RECT  8.784 0 8.808 0.084 ;
    END
  END o[52]
  PIN o[53]
    DIRECTION OUTPUT ;
    USE SIGNAL ;
    PORT
      LAYER M5 ;
        RECT  8.88 0 8.904 0.084 ;
    END
  END o[53]
  PIN o[54]
    DIRECTION OUTPUT ;
    USE SIGNAL ;
    PORT
      LAYER M5 ;
        RECT  8.976 0 9 0.084 ;
    END
  END o[54]
  PIN o[55]
    DIRECTION OUTPUT ;
    USE SIGNAL ;
    PORT
      LAYER M5 ;
        RECT  9.072 0 9.096 0.084 ;
    END
  END o[55]
  PIN o[56]
    DIRECTION OUTPUT ;
    USE SIGNAL ;
    PORT
      LAYER M5 ;
        RECT  9.168 0 9.192 0.084 ;
    END
  END o[56]
  PIN o[57]
    DIRECTION OUTPUT ;
    USE SIGNAL ;
    PORT
      LAYER M5 ;
        RECT  9.264 0 9.288 0.084 ;
    END
  END o[57]
  PIN o[58]
    DIRECTION OUTPUT ;
    USE SIGNAL ;
    PORT
      LAYER M5 ;
        RECT  9.36 0 9.384 0.084 ;
    END
  END o[58]
  PIN o[59]
    DIRECTION OUTPUT ;
    USE SIGNAL ;
    PORT
      LAYER M5 ;
        RECT  9.456 0 9.48 0.084 ;
    END
  END o[59]
  PIN o[5]
    DIRECTION OUTPUT ;
    USE SIGNAL ;
    PORT
      LAYER M5 ;
        RECT  16.56 0 16.584 0.084 ;
    END
  END o[5]
  PIN o[60]
    DIRECTION OUTPUT ;
    USE SIGNAL ;
    PORT
      LAYER M5 ;
        RECT  9.552 0 9.576 0.084 ;
    END
  END o[60]
  PIN o[61]
    DIRECTION OUTPUT ;
    USE SIGNAL ;
    PORT
      LAYER M5 ;
        RECT  9.648 0 9.672 0.084 ;
    END
  END o[61]
  PIN o[62]
    DIRECTION OUTPUT ;
    USE SIGNAL ;
    PORT
      LAYER M5 ;
        RECT  9.744 0 9.768 0.084 ;
    END
  END o[62]
  PIN o[63]
    DIRECTION OUTPUT ;
    USE SIGNAL ;
    PORT
      LAYER M5 ;
        RECT  9.84 0 9.864 0.084 ;
    END
  END o[63]
  PIN o[64]
    DIRECTION OUTPUT ;
    USE SIGNAL ;
    PORT
      LAYER M5 ;
        RECT  9.936 0 9.96 0.084 ;
    END
  END o[64]
  PIN o[65]
    DIRECTION OUTPUT ;
    USE SIGNAL ;
    PORT
      LAYER M5 ;
        RECT  10.032 0 10.056 0.084 ;
    END
  END o[65]
  PIN o[66]
    DIRECTION OUTPUT ;
    USE SIGNAL ;
    PORT
      LAYER M5 ;
        RECT  10.128 0 10.152 0.084 ;
    END
  END o[66]
  PIN o[67]
    DIRECTION OUTPUT ;
    USE SIGNAL ;
    PORT
      LAYER M5 ;
        RECT  10.224 0 10.248 0.084 ;
    END
  END o[67]
  PIN o[68]
    DIRECTION OUTPUT ;
    USE SIGNAL ;
    PORT
      LAYER M5 ;
        RECT  10.32 0 10.344 0.084 ;
    END
  END o[68]
  PIN o[69]
    DIRECTION OUTPUT ;
    USE SIGNAL ;
    PORT
      LAYER M5 ;
        RECT  10.416 0 10.44 0.084 ;
    END
  END o[69]
  PIN o[6]
    DIRECTION OUTPUT ;
    USE SIGNAL ;
    PORT
      LAYER M5 ;
        RECT  16.656 0 16.68 0.084 ;
    END
  END o[6]
  PIN o[70]
    DIRECTION OUTPUT ;
    USE SIGNAL ;
    PORT
      LAYER M5 ;
        RECT  10.512 0 10.536 0.084 ;
    END
  END o[70]
  PIN o[71]
    DIRECTION OUTPUT ;
    USE SIGNAL ;
    PORT
      LAYER M5 ;
        RECT  10.608 0 10.632 0.084 ;
    END
  END o[71]
  PIN o[72]
    DIRECTION OUTPUT ;
    USE SIGNAL ;
    PORT
      LAYER M5 ;
        RECT  10.704 0 10.728 0.084 ;
    END
  END o[72]
  PIN o[73]
    DIRECTION OUTPUT ;
    USE SIGNAL ;
    PORT
      LAYER M5 ;
        RECT  10.8 0 10.824 0.084 ;
    END
  END o[73]
  PIN o[74]
    DIRECTION OUTPUT ;
    USE SIGNAL ;
    PORT
      LAYER M5 ;
        RECT  10.896 0 10.92 0.084 ;
    END
  END o[74]
  PIN o[75]
    DIRECTION OUTPUT ;
    USE SIGNAL ;
    PORT
      LAYER M5 ;
        RECT  10.992 0 11.016 0.084 ;
    END
  END o[75]
  PIN o[76]
    DIRECTION OUTPUT ;
    USE SIGNAL ;
    PORT
      LAYER M5 ;
        RECT  11.088 0 11.112 0.084 ;
    END
  END o[76]
  PIN o[77]
    DIRECTION OUTPUT ;
    USE SIGNAL ;
    PORT
      LAYER M5 ;
        RECT  11.184 0 11.208 0.084 ;
    END
  END o[77]
  PIN o[78]
    DIRECTION OUTPUT ;
    USE SIGNAL ;
    PORT
      LAYER M5 ;
        RECT  11.28 0 11.304 0.084 ;
    END
  END o[78]
  PIN o[79]
    DIRECTION OUTPUT ;
    USE SIGNAL ;
    PORT
      LAYER M5 ;
        RECT  11.376 0 11.4 0.084 ;
    END
  END o[79]
  PIN o[7]
    DIRECTION OUTPUT ;
    USE SIGNAL ;
    PORT
      LAYER M5 ;
        RECT  16.752 0 16.776 0.084 ;
    END
  END o[7]
  PIN o[80]
    DIRECTION OUTPUT ;
    USE SIGNAL ;
    PORT
      LAYER M5 ;
        RECT  11.472 0 11.496 0.084 ;
    END
  END o[80]
  PIN o[81]
    DIRECTION OUTPUT ;
    USE SIGNAL ;
    PORT
      LAYER M5 ;
        RECT  11.568 0 11.592 0.084 ;
    END
  END o[81]
  PIN o[82]
    DIRECTION OUTPUT ;
    USE SIGNAL ;
    PORT
      LAYER M5 ;
        RECT  11.664 0 11.688 0.084 ;
    END
  END o[82]
  PIN o[83]
    DIRECTION OUTPUT ;
    USE SIGNAL ;
    PORT
      LAYER M5 ;
        RECT  11.76 0 11.784 0.084 ;
    END
  END o[83]
  PIN o[84]
    DIRECTION OUTPUT ;
    USE SIGNAL ;
    PORT
      LAYER M5 ;
        RECT  11.856 0 11.88 0.084 ;
    END
  END o[84]
  PIN o[85]
    DIRECTION OUTPUT ;
    USE SIGNAL ;
    PORT
      LAYER M5 ;
        RECT  11.952 0 11.976 0.084 ;
    END
  END o[85]
  PIN o[86]
    DIRECTION OUTPUT ;
    USE SIGNAL ;
    PORT
      LAYER M5 ;
        RECT  12.048 0 12.072 0.084 ;
    END
  END o[86]
  PIN o[87]
    DIRECTION OUTPUT ;
    USE SIGNAL ;
    PORT
      LAYER M5 ;
        RECT  12.144 0 12.168 0.084 ;
    END
  END o[87]
  PIN o[88]
    DIRECTION OUTPUT ;
    USE SIGNAL ;
    PORT
      LAYER M5 ;
        RECT  12.24 0 12.264 0.084 ;
    END
  END o[88]
  PIN o[89]
    DIRECTION OUTPUT ;
    USE SIGNAL ;
    PORT
      LAYER M5 ;
        RECT  12.336 0 12.36 0.084 ;
    END
  END o[89]
  PIN o[8]
    DIRECTION OUTPUT ;
    USE SIGNAL ;
    PORT
      LAYER M5 ;
        RECT  16.848 0 16.872 0.084 ;
    END
  END o[8]
  PIN o[90]
    DIRECTION OUTPUT ;
    USE SIGNAL ;
    PORT
      LAYER M5 ;
        RECT  12.432 0 12.456 0.084 ;
    END
  END o[90]
  PIN o[91]
    DIRECTION OUTPUT ;
    USE SIGNAL ;
    PORT
      LAYER M5 ;
        RECT  12.528 0 12.552 0.084 ;
    END
  END o[91]
  PIN o[92]
    DIRECTION OUTPUT ;
    USE SIGNAL ;
    PORT
      LAYER M5 ;
        RECT  12.624 0 12.648 0.084 ;
    END
  END o[92]
  PIN o[93]
    DIRECTION OUTPUT ;
    USE SIGNAL ;
    PORT
      LAYER M5 ;
        RECT  12.72 0 12.744 0.084 ;
    END
  END o[93]
  PIN o[94]
    DIRECTION OUTPUT ;
    USE SIGNAL ;
    PORT
      LAYER M5 ;
        RECT  12.816 0 12.84 0.084 ;
    END
  END o[94]
  PIN o[95]
    DIRECTION OUTPUT ;
    USE SIGNAL ;
    PORT
      LAYER M5 ;
        RECT  12.912 0 12.936 0.084 ;
    END
  END o[95]
  PIN o[96]
    DIRECTION OUTPUT ;
    USE SIGNAL ;
    PORT
      LAYER M5 ;
        RECT  13.008 0 13.032 0.084 ;
    END
  END o[96]
  PIN o[97]
    DIRECTION OUTPUT ;
    USE SIGNAL ;
    PORT
      LAYER M5 ;
        RECT  13.104 0 13.128 0.084 ;
    END
  END o[97]
  PIN o[98]
    DIRECTION OUTPUT ;
    USE SIGNAL ;
    PORT
      LAYER M5 ;
        RECT  13.2 0 13.224 0.084 ;
    END
  END o[98]
  PIN o[99]
    DIRECTION OUTPUT ;
    USE SIGNAL ;
    PORT
      LAYER M5 ;
        RECT  13.296 0 13.32 0.084 ;
    END
  END o[99]
  PIN o[9]
    DIRECTION OUTPUT ;
    USE SIGNAL ;
    PORT
      LAYER M5 ;
        RECT  16.944 0 16.968 0.084 ;
    END
  END o[9]
  PIN rs
    DIRECTION INPUT ;
    USE SIGNAL ;
    PORT
      LAYER M4 ;
        RECT  0 11.952 0.084 11.976 ;
    END
  END rs
  PIN VDD
    DIRECTION INOUT ;
    USE POWER ;
    PORT
      LAYER M5 ;
        RECT  18.792 2.151 18.912 19.449 ;
        RECT  16.092 2.151 16.212 19.449 ;
        RECT  13.392 2.151 13.512 19.449 ;
        RECT  10.692 2.151 10.812 19.449 ;
        RECT  7.992 2.151 8.112 19.449 ;
        RECT  5.292 2.151 5.412 19.449 ;
        RECT  2.592 2.151 2.712 19.449 ;
    END
  END VDD
  PIN VSS
    DIRECTION INOUT ;
    USE GROUND ;
    PORT
      LAYER M5 ;
        RECT  18.6 2.137 18.72 19.463 ;
        RECT  15.9 2.137 16.02 19.463 ;
        RECT  13.2 2.137 13.32 19.463 ;
        RECT  10.5 2.137 10.62 19.463 ;
        RECT  7.8 2.137 7.92 19.463 ;
        RECT  5.1 2.137 5.22 19.463 ;
        RECT  2.4 2.137 2.52 19.463 ;
    END
  END VSS
  # OT_OBS_CLOSED layer=M5 d_um=1.536 added=26
  OBS
    LAYER RVTN ;
     RECT  2.16 2.16 19.44 2.295 ;
     RECT  2.16 2.565 19.44 2.835 ;
     RECT  2.16 3.105 19.44 3.375 ;
     RECT  2.16 3.645 19.44 3.915 ;
     RECT  2.16 4.185 19.44 4.455 ;
     RECT  2.16 4.725 19.44 4.995 ;
     RECT  2.16 5.265 19.44 5.535 ;
     RECT  2.16 5.805 19.44 6.075 ;
     RECT  2.16 6.345 19.44 6.615 ;
     RECT  2.16 6.885 19.44 7.155 ;
     RECT  2.16 7.425 19.44 7.695 ;
     RECT  2.16 7.965 19.44 8.235 ;
     RECT  2.16 8.505 19.44 8.775 ;
     RECT  2.16 9.045 19.44 9.315 ;
     RECT  2.16 9.585 19.44 9.855 ;
     RECT  2.16 10.125 19.44 10.395 ;
     RECT  2.16 10.665 19.44 10.935 ;
     RECT  2.16 11.205 19.44 11.475 ;
     RECT  2.16 11.745 19.44 12.015 ;
     RECT  2.16 12.285 19.44 12.555 ;
     RECT  2.16 12.825 19.44 13.095 ;
     RECT  2.16 13.365 19.44 13.635 ;
     RECT  2.16 13.905 19.44 14.175 ;
     RECT  2.16 14.445 19.44 14.715 ;
     RECT  2.16 14.985 19.44 15.255 ;
     RECT  2.16 15.525 19.44 15.795 ;
     RECT  2.16 16.065 19.44 16.335 ;
     RECT  2.16 16.605 19.44 16.875 ;
     RECT  2.16 17.145 19.44 17.415 ;
     RECT  2.16 17.685 19.44 17.955 ;
     RECT  2.16 18.225 19.44 18.495 ;
     RECT  2.16 18.765 19.44 19.035 ;
     RECT  2.16 19.305 19.44 19.44 ;
    LAYER RVTP ;
     RECT  2.16 2.295 19.44 2.565 ;
     RECT  2.16 2.835 19.44 3.105 ;
     RECT  2.16 3.375 19.44 3.645 ;
     RECT  2.16 3.915 19.44 4.185 ;
     RECT  2.16 4.455 19.44 4.725 ;
     RECT  2.16 4.995 19.44 5.265 ;
     RECT  2.16 5.535 19.44 5.805 ;
     RECT  2.16 6.075 19.44 6.345 ;
     RECT  2.16 6.615 19.44 6.885 ;
     RECT  2.16 7.155 19.44 7.425 ;
     RECT  2.16 7.695 19.44 7.965 ;
     RECT  2.16 8.235 19.44 8.505 ;
     RECT  2.16 8.775 19.44 9.045 ;
     RECT  2.16 9.315 19.44 9.585 ;
     RECT  2.16 9.855 19.44 10.125 ;
     RECT  2.16 10.395 19.44 10.665 ;
     RECT  2.16 10.935 19.44 11.205 ;
     RECT  2.16 11.475 19.44 11.745 ;
     RECT  2.16 12.015 19.44 12.285 ;
     RECT  2.16 12.555 19.44 12.825 ;
     RECT  2.16 13.095 19.44 13.365 ;
     RECT  2.16 13.635 19.44 13.905 ;
     RECT  2.16 14.175 19.44 14.445 ;
     RECT  2.16 14.715 19.44 14.985 ;
     RECT  2.16 15.255 19.44 15.525 ;
     RECT  2.16 15.795 19.44 16.065 ;
     RECT  2.16 16.335 19.44 16.605 ;
     RECT  2.16 16.875 19.44 17.145 ;
     RECT  2.16 17.415 19.44 17.685 ;
     RECT  2.16 17.955 19.44 18.225 ;
     RECT  2.16 18.495 19.44 18.765 ;
     RECT  2.16 19.035 19.44 19.305 ;
    LAYER M1 ;
     RECT  2.16 2.151 19.44 19.449 ;
    LAYER M2 ;
     RECT  2.16 2.151 4.963 19.449 ;
     RECT  4.963 2.106 5.431 19.449 ;
     RECT  5.431 1.836 5.683 19.449 ;
     RECT  5.683 1.8 8.663 19.449 ;
     RECT  8.663 1.836 9.131 19.449 ;
     RECT  9.131 1.881 9.563 19.449 ;
     RECT  9.563 2.106 11.227 19.449 ;
     RECT  11.227 2.034 12.659 19.449 ;
     RECT  12.659 2.151 15.799 19.449 ;
     RECT  15.799 2.106 16.475 19.449 ;
     RECT  16.475 2.151 19.44 19.449 ;
     RECT  19.44 6.354 19.751 8.838 ;
     RECT  19.44 2.646 20.003 4.284 ;
     RECT  20.003 2.646 20.111 3.132 ;
     RECT  19.751 6.894 20.111 8.838 ;
     RECT  20.111 2.646 20.147 2.754 ;
     RECT  20.111 6.894 20.147 8.694 ;
     RECT  20.147 6.894 20.183 7.884 ;
     RECT  20.147 2.646 20.219 2.664 ;
     RECT  19.44 13.266 20.219 13.626 ;
     RECT  20.147 8.676 20.255 8.694 ;
     RECT  20.003 3.888 20.291 4.284 ;
     RECT  19.44 15.696 20.291 15.714 ;
     RECT  20.291 3.888 20.543 4.212 ;
     RECT  20.219 13.608 20.543 13.626 ;
     RECT  20.543 4.194 20.579 4.212 ;
     RECT  20.183 6.894 20.579 7.722 ;
     RECT  20.579 6.894 20.615 7.65 ;
     RECT  20.615 7.434 20.651 7.65 ;
     RECT  20.651 7.47 20.687 7.65 ;
     RECT  20.687 7.47 20.723 7.524 ;
     RECT  20.723 7.506 20.759 7.524 ;
    LAYER M3 ;
     RECT  20.232 0.091 20.25 0.139 ;
     RECT  8.316 0.091 8.334 0.187 ;
     RECT  12.708 0.091 12.942 0.187 ;
     RECT  8.316 0.187 9.018 0.221 ;
     RECT  12.636 0.187 12.942 0.221 ;
     RECT  14.832 0.091 15.606 0.221 ;
     RECT  13.716 0.091 13.734 0.269 ;
     RECT  15.12 0.221 15.606 0.269 ;
     RECT  12.636 0.221 12.87 0.317 ;
     RECT  15.516 0.269 15.606 0.331 ;
     RECT  19.62 0.139 20.25 0.331 ;
     RECT  9 0.221 9.018 0.365 ;
     RECT  12.636 0.317 12.654 0.365 ;
     RECT  18.864 0.235 18.882 0.365 ;
     RECT  15.516 0.331 15.642 0.509 ;
     RECT  7.092 0.091 7.11 0.523 ;
     RECT  17.712 0.091 17.73 0.571 ;
     RECT  6.228 0.139 6.246 1.147 ;
     RECT  7.092 0.523 7.47 1.147 ;
     RECT  16.488 0.331 16.506 1.181 ;
     RECT  17.388 0.571 18.126 1.195 ;
     RECT  8.712 1.147 8.982 1.723 ;
     RECT  15.624 0.509 15.642 1.723 ;
     RECT  19.62 0.331 20.754 1.723 ;
     RECT  6.228 1.147 7.794 1.795 ;
     RECT  8.712 1.723 9.306 1.795 ;
     RECT  5.688 1.795 7.794 1.831 ;
     RECT  8.64 1.795 9.306 1.876 ;
     RECT  5.436 1.831 7.794 1.957 ;
     RECT  8.64 1.876 9.558 1.957 ;
     RECT  13.644 1.723 13.662 1.963 ;
     RECT  10.656 1.963 10.674 2.011 ;
     RECT  10.332 2.011 10.854 2.029 ;
     RECT  12.168 1.723 12.186 2.029 ;
     RECT  13.356 1.963 13.662 2.029 ;
     RECT  5.436 1.957 9.558 2.101 ;
     RECT  10.332 2.029 11.25 2.101 ;
     RECT  12.168 2.029 13.662 2.101 ;
     RECT  15.624 1.723 15.822 2.101 ;
     RECT  17.388 1.195 18.27 2.143 ;
     RECT  19.008 1.723 20.754 2.143 ;
     RECT  4.968 2.101 9.558 2.191 ;
     RECT  10.332 2.101 13.662 2.191 ;
     RECT  15.624 2.101 16.47 2.191 ;
     RECT  17.388 2.143 20.754 2.191 ;
     RECT  2.415 2.143 2.505 2.413 ;
     RECT  4.968 2.191 20.754 3.109 ;
     RECT  4.428 3.109 20.754 3.271 ;
     RECT  4.392 3.271 20.754 7.529 ;
     RECT  4.392 7.529 20.682 7.655 ;
     RECT  4.392 7.655 20.574 7.727 ;
     RECT  4.392 7.727 20.538 8.159 ;
     RECT  4.392 8.159 19.314 8.429 ;
     RECT  4.392 8.429 19.278 8.501 ;
     RECT  20.052 8.159 20.538 8.771 ;
     RECT  20.088 8.771 20.538 8.843 ;
     RECT  2.415 2.413 2.697 11.947 ;
     RECT  2.304 11.947 2.697 12.181 ;
     RECT  2.304 12.181 2.898 12.361 ;
     RECT  2.304 12.361 3.078 12.451 ;
     RECT  4.392 8.501 19.098 12.451 ;
     RECT  2.304 12.451 19.098 12.515 ;
     RECT  2.34 12.515 19.098 13.085 ;
     RECT  20.196 8.843 20.538 13.289 ;
     RECT  2.415 13.085 19.098 13.441 ;
     RECT  20.268 13.289 20.538 13.631 ;
     RECT  2.415 13.441 19.17 15.601 ;
     RECT  20.268 13.631 20.286 15.719 ;
     RECT  2.415 15.601 19.242 15.899 ;
     RECT  2.415 15.899 19.17 16.169 ;
     RECT  2.415 16.169 19.098 16.231 ;
     RECT  2.34 16.231 19.098 16.331 ;
     RECT  2.415 16.331 19.098 17.083 ;
     RECT  2.415 17.083 19.242 17.609 ;
     RECT  2.415 17.609 19.206 17.995 ;
     RECT  2.34 17.995 19.206 18.149 ;
     RECT  2.34 18.149 18.897 18.157 ;
     RECT  2.304 18.157 18.897 18.461 ;
     RECT  2.34 18.461 18.897 19.187 ;
     RECT  2.34 19.187 18.705 19.229 ;
     RECT  2.34 19.229 5.778 19.301 ;
     RECT  6.804 19.229 18.705 19.325 ;
     RECT  10.332 19.325 18.705 19.337 ;
     RECT  2.376 19.301 5.778 19.373 ;
     RECT  6.804 19.325 9.342 19.373 ;
     RECT  10.332 19.337 14.562 19.373 ;
     RECT  15.876 19.337 18.705 19.373 ;
     RECT  15.915 19.373 17.082 19.379 ;
     RECT  12.564 19.373 14.562 19.421 ;
     RECT  5.115 19.373 5.274 19.457 ;
     RECT  12.564 19.421 13.734 19.457 ;
     RECT  15.915 19.379 16.938 19.457 ;
     RECT  18.615 19.373 18.705 19.457 ;
     RECT  2.376 19.373 3.294 19.469 ;
     RECT  10.44 19.373 10.818 19.565 ;
     RECT  13.536 19.457 13.734 19.565 ;
     RECT  2.376 19.469 2.754 19.613 ;
     RECT  5.256 19.457 5.274 19.613 ;
     RECT  7.596 19.373 8.586 19.613 ;
     RECT  2.736 19.613 2.754 19.661 ;
     RECT  10.476 19.565 10.494 19.661 ;
     RECT  9.324 19.373 9.342 19.949 ;
     RECT  7.596 19.613 7.614 19.997 ;
     RECT  8.46 19.613 8.586 19.997 ;
     RECT  16.596 19.457 16.938 19.997 ;
     RECT  8.568 19.997 8.586 20.525 ;
     RECT  12.564 19.457 12.582 20.573 ;
     RECT  16.92 19.997 16.938 20.573 ;
     RECT  5.616 21.019 5.634 21.211 ;
     RECT  5.616 21.211 5.85 21.307 ;
     RECT  5.616 21.307 6.39 21.389 ;
     RECT  6.228 21.389 6.39 21.485 ;
     RECT  13.716 19.565 13.734 21.485 ;
    LAYER M4 ;
     RECT  0.084 11.856 0.179 11.88 ;
     RECT  0.06 11.88 0.179 11.952 ;
     RECT  0.084 11.952 0.179 11.976 ;
     RECT  2.293 18.432 2.365 18.456 ;
     RECT  0.179 11.952 2.408 11.976 ;
     RECT  2.329 13.056 2.408 13.08 ;
     RECT  0.133 14.4 2.408 14.424 ;
     RECT  2.365 18.432 2.408 19.608 ;
     RECT  2.408 2.148 2.512 19.608 ;
     RECT  2.512 2.418 2.684 19.608 ;
     RECT  2.684 2.418 2.704 19.656 ;
     RECT  2.704 18.816 2.771 19.656 ;
     RECT  2.771 18.816 2.819 19.56 ;
     RECT  2.704 13.056 2.915 17.688 ;
     RECT  2.915 13.68 2.953 17.688 ;
     RECT  2.953 13.68 3.305 14.808 ;
     RECT  2.953 15.936 3.377 17.688 ;
     RECT  2.819 18.816 3.443 19.464 ;
     RECT  3.377 15.936 3.485 17.064 ;
     RECT  3.443 18.816 3.781 19.368 ;
     RECT  3.305 13.872 4.061 14.808 ;
     RECT  3.485 15.984 4.405 17.064 ;
     RECT  3.781 18.192 4.405 19.368 ;
     RECT  4.061 13.872 4.417 14.424 ;
     RECT  3.925 12.336 4.501 12.36 ;
     RECT  4.417 13.824 4.501 14.424 ;
     RECT  3.589 21.408 4.885 21.432 ;
     RECT  4.885 21.312 5.027 21.432 ;
     RECT  4.501 12.336 5.065 14.424 ;
     RECT  4.405 15.984 5.065 19.368 ;
     RECT  5.065 12.336 5.108 19.368 ;
     RECT  5.108 2.148 5.125 19.452 ;
     RECT  5.125 2.148 5.212 19.608 ;
     RECT  5.027 21.312 5.221 21.384 ;
     RECT  5.212 2.418 5.285 19.608 ;
     RECT  5.285 2.418 5.404 19.368 ;
     RECT  5.221 20.976 5.699 21.384 ;
     RECT  5.699 21.12 5.747 21.384 ;
     RECT  5.747 21.216 5.989 21.384 ;
     RECT  5.989 21.216 6.445 21.48 ;
     RECT  5.404 2.544 6.577 2.856 ;
     RECT  5.404 3.84 6.577 3.864 ;
     RECT  6.445 21.216 6.611 21.432 ;
     RECT  6.611 21.36 6.755 21.432 ;
     RECT  5.404 11.904 6.853 19.368 ;
     RECT  6.853 11.568 6.865 19.368 ;
     RECT  6.829 1.152 6.912 1.176 ;
     RECT  6.865 11.424 7.045 19.368 ;
     RECT  6.217 0.144 7.081 0.168 ;
     RECT  6.912 1.152 7.093 1.224 ;
     RECT  6.577 2.544 7.093 3.864 ;
     RECT  6.997 5.088 7.093 5.112 ;
     RECT  7.081 0.096 7.187 0.168 ;
     RECT  7.093 1.152 7.189 3.864 ;
     RECT  7.187 0.144 7.369 0.168 ;
     RECT  7.189 1.152 7.369 3.96 ;
     RECT  7.381 6.816 7.429 6.84 ;
     RECT  7.369 0.144 7.477 3.96 ;
     RECT  7.045 11.376 7.477 19.368 ;
     RECT  7.477 10.848 7.585 19.368 ;
     RECT  7.585 10.848 7.669 19.992 ;
     RECT  7.477 0.144 7.808 4.008 ;
     RECT  7.093 5.04 7.808 5.112 ;
     RECT  7.429 6.72 7.808 6.84 ;
     RECT  7.669 10.608 7.808 19.992 ;
     RECT  7.808 0.144 8.104 19.992 ;
     RECT  8.104 0.144 8.273 6.84 ;
     RECT  8.273 0.144 8.29 5.88 ;
     RECT  8.104 10.272 8.291 19.992 ;
     RECT  8.29 0.096 8.531 5.88 ;
     RECT  8.291 14.304 8.557 19.992 ;
     RECT  6.755 21.408 8.557 21.432 ;
     RECT  8.557 14.304 8.867 21.432 ;
     RECT  8.531 0.144 8.993 5.88 ;
     RECT  8.993 0.144 9.059 0.36 ;
     RECT  9.059 0.144 9.107 0.264 ;
     RECT  8.291 10.272 9.457 13.32 ;
     RECT  8.867 14.304 9.491 20.52 ;
     RECT  9.457 9.696 9.541 13.32 ;
     RECT  8.104 7.92 9.829 7.944 ;
     RECT  8.993 1.728 9.884 5.88 ;
     RECT  9.829 7.344 9.884 7.944 ;
     RECT  9.541 10.32 9.889 13.32 ;
     RECT  9.491 14.304 9.889 19.944 ;
     RECT  9.884 1.728 10.021 7.944 ;
     RECT  9.107 0.144 10.117 0.216 ;
     RECT  10.021 1.248 10.117 7.944 ;
     RECT  10.117 0.144 10.259 7.944 ;
     RECT  10.259 0.144 10.451 0.264 ;
     RECT  10.259 1.68 10.508 7.944 ;
     RECT  9.889 10.32 10.508 19.944 ;
     RECT  10.508 1.68 10.547 19.944 ;
     RECT  10.547 1.68 10.643 19.656 ;
     RECT  10.643 1.68 10.804 19.56 ;
     RECT  10.804 9.936 10.873 19.56 ;
     RECT  10.873 9.936 11.267 19.368 ;
     RECT  10.451 0.144 11.363 0.168 ;
     RECT  10.804 1.68 11.459 6.36 ;
     RECT  11.413 21.408 11.557 21.432 ;
     RECT  10.804 7.344 11.657 7.944 ;
     RECT  11.557 21.312 11.699 21.432 ;
     RECT  11.699 21.312 11.747 21.336 ;
     RECT  11.657 7.344 11.837 7.368 ;
     RECT  11.459 1.728 12.197 6.36 ;
     RECT  12.517 0.288 12.581 0.312 ;
     RECT  12.517 20.544 12.604 20.568 ;
     RECT  12.581 0.192 12.625 0.312 ;
     RECT  12.625 0.192 12.658 0.36 ;
     RECT  12.658 0.096 12.755 0.36 ;
     RECT  12.197 2.304 12.805 6.36 ;
     RECT  11.267 9.936 12.805 17.832 ;
     RECT  11.267 18.816 12.805 19.368 ;
     RECT  12.755 0.096 12.947 0.312 ;
     RECT  12.805 9.936 13.045 19.368 ;
     RECT  12.805 2.304 13.189 6.408 ;
     RECT  13.189 2.016 13.208 6.408 ;
     RECT  12.697 7.392 13.208 7.416 ;
     RECT  13.045 9.936 13.208 19.608 ;
     RECT  13.208 2.016 13.235 19.608 ;
     RECT  13.235 2.016 13.285 19.56 ;
     RECT  13.285 1.968 13.477 19.56 ;
     RECT  13.477 1.728 13.504 19.56 ;
     RECT  13.504 10.944 13.565 19.56 ;
     RECT  12.853 21.216 13.573 21.432 ;
     RECT  13.573 21.216 13.619 21.48 ;
     RECT  13.565 10.944 13.637 19.416 ;
     RECT  13.504 1.728 13.645 6.888 ;
     RECT  13.637 11.376 13.715 19.416 ;
     RECT  12.947 0.096 13.745 0.264 ;
     RECT  13.619 21.312 13.745 21.48 ;
     RECT  13.715 11.424 13.811 19.416 ;
     RECT  13.811 11.424 13.889 18.216 ;
     RECT  13.889 11.424 13.897 17.448 ;
     RECT  13.745 21.312 13.955 21.432 ;
     RECT  13.955 21.312 14.243 21.336 ;
     RECT  13.897 12 14.537 17.448 ;
     RECT  13.645 1.728 14.581 6.456 ;
     RECT  13.811 19.248 14.617 19.416 ;
     RECT  14.537 12.48 14.675 17.448 ;
     RECT  14.675 15.792 14.681 17.448 ;
     RECT  14.617 19.248 14.681 19.368 ;
     RECT  14.681 19.296 14.753 19.368 ;
     RECT  14.581 1.152 14.771 6.456 ;
     RECT  13.745 0.096 14.821 0.12 ;
     RECT  14.771 1.728 15.061 6.456 ;
     RECT  14.675 12.48 15.505 14.568 ;
     RECT  14.681 17.04 15.729 17.448 ;
     RECT  15.505 12 15.793 14.568 ;
     RECT  15.793 12 15.829 14.664 ;
     RECT  14.681 15.792 15.829 16.008 ;
     RECT  15.061 1.728 15.868 6.888 ;
     RECT  15.868 2.148 15.901 6.888 ;
     RECT  15.901 2.148 15.908 7.128 ;
     RECT  15.289 9.648 15.908 9.672 ;
     RECT  15.829 12 15.908 16.008 ;
     RECT  15.729 17.04 15.908 18.168 ;
     RECT  14.753 19.344 15.908 19.368 ;
     RECT  15.908 2.148 16.012 19.452 ;
     RECT  16.012 2.352 16.204 19.452 ;
     RECT  16.204 2.352 16.403 7.992 ;
     RECT  14.821 0.096 16.46 0.504 ;
     RECT  16.204 19.296 16.585 19.452 ;
     RECT  16.403 2.352 16.595 6.936 ;
     RECT  16.403 7.968 16.777 7.992 ;
     RECT  16.585 19.296 16.909 19.992 ;
     RECT  16.46 0.096 17.029 1.176 ;
     RECT  16.595 2.352 17.029 6.888 ;
     RECT  16.909 19.296 17.267 20.568 ;
     RECT  17.267 19.296 17.363 19.992 ;
     RECT  16.204 17.904 17.381 18.168 ;
     RECT  17.363 19.296 17.585 19.368 ;
     RECT  17.029 0.096 17.701 6.888 ;
     RECT  17.701 0.096 17.741 6.936 ;
     RECT  16.204 12.864 17.809 16.92 ;
     RECT  17.381 17.904 17.809 17.928 ;
     RECT  17.741 0.144 17.917 6.936 ;
     RECT  17.917 0.144 17.941 7.464 ;
     RECT  17.941 0.144 17.989 7.896 ;
     RECT  17.989 0.144 18.608 7.992 ;
     RECT  17.881 9.696 18.608 9.72 ;
     RECT  17.809 12.864 18.608 17.928 ;
     RECT  17.585 19.008 18.608 19.368 ;
     RECT  18.608 0.144 18.712 19.452 ;
     RECT  18.712 0.144 18.904 19.182 ;
     RECT  18.904 0.144 19.043 8.568 ;
     RECT  19.043 6.288 19.139 8.568 ;
     RECT  19.043 0.144 19.181 4.92 ;
     RECT  19.139 6.288 19.189 6.6 ;
     RECT  19.139 7.68 19.235 8.568 ;
     RECT  19.189 6.288 19.331 6.312 ;
     RECT  19.181 0.144 19.333 4.536 ;
     RECT  19.235 7.968 19.571 8.568 ;
     RECT  18.904 12.864 19.619 14.952 ;
     RECT  19.619 12.864 19.667 14.76 ;
     RECT  19.667 13.68 19.715 14.76 ;
     RECT  19.571 8.496 19.763 8.568 ;
     RECT  19.763 8.496 20.003 8.52 ;
     RECT  18.904 16.032 20.051 17.64 ;
     RECT  19.333 0.096 20.099 4.536 ;
     RECT  20.051 17.088 20.099 17.64 ;
     RECT  20.099 0.096 20.147 3.672 ;
     RECT  20.051 16.032 20.147 16.056 ;
     RECT  19.715 14.256 20.195 14.76 ;
     RECT  20.147 0.096 20.243 3.432 ;
     RECT  20.195 14.736 20.243 14.76 ;
     RECT  20.243 0.096 20.261 2.952 ;
     RECT  20.099 17.616 20.291 17.64 ;
     RECT  20.261 0.336 20.621 2.952 ;
     RECT  20.621 1.776 20.657 2.952 ;
     RECT  20.657 2.928 20.693 2.952 ;
     RECT  20.657 1.776 20.729 1.8 ;
     RECT  20.621 0.336 20.765 0.36 ;
    LAYER M5 ;
     RECT  6.888 0.016 6.96 0.084 ;
     RECT  6.984 0.016 7.056 0.084 ;
     RECT  7.08 0.016 7.152 0.084 ;
     RECT  7.176 0.016 7.248 0.084 ;
     RECT  7.272 0.016 7.344 0.084 ;
     RECT  7.368 0.016 7.44 0.084 ;
     RECT  7.464 0.016 7.536 0.084 ;
     RECT  7.56 0.016 7.632 0.084 ;
     RECT  7.656 0.016 7.728 0.084 ;
     RECT  7.752 0.016 7.824 0.084 ;
     RECT  7.848 0.016 7.92 0.084 ;
     RECT  7.944 0.016 8.016 0.084 ;
     RECT  8.04 0.016 8.112 0.084 ;
     RECT  8.136 0.016 8.208 0.084 ;
     RECT  8.232 0.016 8.304 0.084 ;
     RECT  8.328 0.016 8.4 0.084 ;
     RECT  8.424 0.016 8.496 0.084 ;
     RECT  8.52 0.016 8.592 0.084 ;
     RECT  8.616 0.016 8.688 0.084 ;
     RECT  8.712 0.016 8.784 0.084 ;
     RECT  8.808 0.016 8.88 0.084 ;
     RECT  8.904 0.016 8.976 0.084 ;
     RECT  9 0.016 9.072 0.084 ;
     RECT  9.096 0.016 9.168 0.084 ;
     RECT  9.192 0.016 9.264 0.084 ;
     RECT  9.288 0.016 9.36 0.084 ;
     RECT  9.384 0.016 9.456 0.084 ;
     RECT  9.48 0.016 9.552 0.084 ;
     RECT  9.576 0.016 9.648 0.084 ;
     RECT  9.672 0.016 9.744 0.084 ;
     RECT  9.768 0.016 9.84 0.084 ;
     RECT  9.864 0.016 9.936 0.084 ;
     RECT  9.96 0.016 10.032 0.084 ;
     RECT  10.056 0.016 10.128 0.084 ;
     RECT  10.152 0.016 10.224 0.084 ;
     RECT  10.248 0.016 10.32 0.084 ;
     RECT  10.344 0.016 10.416 0.084 ;
     RECT  10.44 0.016 10.512 0.084 ;
     RECT  10.536 0.016 10.608 0.084 ;
     RECT  10.632 0.016 10.704 0.084 ;
     RECT  10.728 0.016 10.8 0.084 ;
     RECT  10.824 0.016 10.896 0.084 ;
     RECT  10.92 0.016 10.992 0.084 ;
     RECT  11.016 0.016 11.088 0.084 ;
     RECT  11.112 0.016 11.184 0.084 ;
     RECT  11.208 0.016 11.28 0.084 ;
     RECT  11.304 0.016 11.376 0.084 ;
     RECT  11.4 0.016 11.472 0.084 ;
     RECT  11.496 0.016 11.568 0.084 ;
     RECT  11.592 0.016 11.664 0.084 ;
     RECT  11.688 0.016 11.76 0.084 ;
     RECT  11.784 0.016 11.856 0.084 ;
     RECT  11.88 0.016 11.952 0.084 ;
     RECT  11.976 0.016 12.048 0.084 ;
     RECT  12.072 0.016 12.144 0.084 ;
     RECT  12.168 0.016 12.24 0.084 ;
     RECT  12.264 0.016 12.336 0.084 ;
     RECT  12.36 0.016 12.432 0.084 ;
     RECT  12.456 0.016 12.528 0.084 ;
     RECT  12.552 0.016 12.624 0.084 ;
     RECT  12.648 0.016 12.72 0.084 ;
     RECT  12.744 0.016 12.816 0.084 ;
     RECT  12.84 0.016 12.912 0.084 ;
     RECT  12.936 0.016 13.008 0.084 ;
     RECT  13.032 0.016 13.104 0.084 ;
     RECT  13.128 0.016 13.2 0.084 ;
     RECT  13.224 0.016 13.296 0.084 ;
     RECT  13.32 0.016 13.392 0.084 ;
     RECT  13.416 0.016 13.488 0.084 ;
     RECT  13.512 0.016 13.584 0.084 ;
     RECT  13.608 0.016 13.68 0.084 ;
     RECT  13.704 0.016 13.776 0.084 ;
     RECT  13.8 0.016 13.872 0.084 ;
     RECT  13.896 0.016 13.968 0.084 ;
     RECT  13.992 0.016 14.064 0.084 ;
     RECT  14.088 0.016 14.16 0.084 ;
     RECT  14.184 0.016 14.256 0.084 ;
     RECT  14.28 0.016 14.352 0.084 ;
     RECT  14.376 0.016 14.448 0.084 ;
     RECT  14.472 0.016 14.544 0.084 ;
     RECT  14.568 0.016 14.64 0.084 ;
     RECT  14.664 0.016 14.736 0.084 ;
     RECT  14.76 0.016 14.832 0.084 ;
     RECT  14.856 0.016 14.928 0.084 ;
     RECT  14.952 0.016 15.024 0.084 ;
     RECT  15.048 0.016 15.12 0.084 ;
     RECT  15.144 0.016 15.216 0.084 ;
     RECT  15.24 0.016 15.312 0.084 ;
     RECT  15.336 0.016 15.408 0.084 ;
     RECT  15.432 0.016 15.504 0.084 ;
     RECT  15.528 0.016 15.6 0.084 ;
     RECT  15.624 0.016 15.696 0.084 ;
     RECT  15.72 0.016 15.792 0.084 ;
     RECT  15.816 0.016 15.888 0.084 ;
     RECT  15.912 0.016 15.984 0.084 ;
     RECT  16.008 0.016 16.08 0.084 ;
     RECT  16.104 0.016 16.176 0.084 ;
     RECT  16.2 0.016 16.272 0.084 ;
     RECT  16.296 0.016 16.368 0.084 ;
     RECT  16.392 0.016 16.464 0.084 ;
     RECT  16.488 0.016 16.56 0.084 ;
     RECT  16.584 0.016 16.656 0.084 ;
     RECT  16.68 0.016 16.752 0.084 ;
     RECT  16.776 0.016 16.848 0.084 ;
     RECT  16.872 0.016 16.944 0.084 ;
     RECT  16.968 0.016 17.04 0.084 ;
     RECT  17.064 0.016 17.136 0.084 ;
     RECT  17.16 0.016 17.232 0.084 ;
     RECT  17.256 0.016 17.328 0.084 ;
     RECT  17.352 0.016 17.424 0.084 ;
     RECT  17.448 0.016 17.52 0.084 ;
     RECT  17.544 0.016 17.616 0.084 ;
     RECT  17.64 0.016 17.712 0.084 ;
     RECT  17.736 0.016 17.808 0.084 ;
     RECT  17.832 0.016 17.904 0.084 ;
     RECT  17.928 0.016 18 0.084 ;
     RECT  18.024 0.016 18.096 0.084 ;
     RECT  18.12 0.016 18.192 0.084 ;
     RECT  18.216 0.016 18.288 0.084 ;
     RECT  18.312 0.016 18.384 0.084 ;
     RECT  18.408 0.016 18.48 0.084 ;
     RECT  18.504 0.016 18.576 0.084 ;
     RECT  18.6 0.016 18.672 0.084 ;
     RECT  18.696 0.016 18.768 0.084 ;
     RECT  18.792 0.016 18.864 0.084 ;
     RECT  18.888 0.016 18.96 0.084 ;
     RECT  18.984 0.016 19.056 0.084 ;
     RECT  19.08 0.016 19.152 0.084 ;
     RECT  19.176 0.016 19.248 0.084 ;
     RECT  19.272 0.016 19.344 0.084 ;
     RECT  19.368 0.016 19.44 0.084 ;
     RECT  19.464 0.016 19.536 0.084 ;
     RECT  19.56 0.016 19.632 0.084 ;
     RECT  19.656 0.016 19.728 0.084 ;
     RECT  19.752 0.016 19.824 0.084 ;
     RECT  6.864 0.084 19.848 0.179 ;
     RECT  6.864 0.179 19.752 1.187 ;
     RECT  6.96 1.187 19.752 1.235 ;
     RECT  2.4 2.137 2.52 2.151 ;
     RECT  5.1 2.137 5.22 2.151 ;
     RECT  5.1 2.151 5.412 2.533 ;
     RECT  7.056 1.235 19.752 2.533 ;
     RECT  5.1 2.533 19.752 2.725 ;
     RECT  5.1 2.725 20.184 2.821 ;
     RECT  5.1 2.821 20.28 6.323 ;
     RECT  12 6.323 20.28 6.371 ;
     RECT  12.768 6.371 20.28 7.427 ;
     RECT  5.1 6.323 10.812 9.925 ;
     RECT  5.1 9.925 11.256 10.117 ;
     RECT  5.1 10.117 11.592 10.165 ;
     RECT  12.96 7.427 20.28 10.165 ;
     RECT  5.1 10.165 20.28 10.979 ;
     RECT  5.1 10.979 12.12 12.469 ;
     RECT  13.2 10.979 20.28 12.469 ;
     RECT  2.4 2.151 2.712 13.045 ;
     RECT  3.936 12.325 3.96 13.045 ;
     RECT  5.1 12.469 20.28 13.045 ;
     RECT  3.936 13.045 20.28 14.291 ;
     RECT  0.144 11.845 0.168 14.435 ;
     RECT  5.1 14.291 20.28 14.867 ;
     RECT  18.6 14.867 20.28 14.963 ;
     RECT  5.1 14.867 17.448 15.443 ;
     RECT  15.024 15.443 17.448 15.587 ;
     RECT  15.024 15.587 16.212 15.827 ;
     RECT  5.1 15.443 13.8 15.973 ;
     RECT  17.424 15.587 17.448 16.115 ;
     RECT  4.944 15.973 13.8 16.261 ;
     RECT  20.016 14.963 20.28 16.835 ;
     RECT  4.896 16.261 13.8 16.837 ;
     RECT  15.9 15.827 16.212 16.885 ;
     RECT  4.896 16.837 13.896 16.933 ;
     RECT  4.896 16.933 13.944 17.029 ;
     RECT  20.064 16.835 20.28 17.123 ;
     RECT  15.9 16.885 16.536 17.413 ;
     RECT  20.256 17.123 20.28 17.651 ;
     RECT  15.792 17.413 16.536 17.939 ;
     RECT  15.792 17.939 16.212 18.179 ;
     RECT  2.4 13.045 2.904 18.181 ;
     RECT  3.936 17.029 14.232 18.181 ;
     RECT  18.6 14.963 18.912 18.997 ;
     RECT  2.4 18.181 14.232 19.237 ;
     RECT  2.4 19.237 14.28 19.285 ;
     RECT  15.9 18.179 16.212 19.285 ;
     RECT  17.616 18.997 18.912 19.285 ;
     RECT  15.9 19.285 18.912 19.449 ;
     RECT  2.4 19.285 14.664 19.463 ;
     RECT  15.9 19.449 16.02 19.463 ;
     RECT  17.04 19.449 18.72 19.463 ;
     RECT  2.448 19.463 14.664 21.516 ;
     RECT  2.472 21.516 2.544 21.584 ;
     RECT  2.568 21.516 2.64 21.584 ;
     RECT  2.664 21.516 2.736 21.584 ;
     RECT  2.76 21.516 2.832 21.584 ;
     RECT  2.856 21.516 2.928 21.584 ;
     RECT  2.952 21.516 3.024 21.584 ;
     RECT  3.048 21.516 3.12 21.584 ;
     RECT  3.144 21.516 3.216 21.584 ;
     RECT  3.24 21.516 3.312 21.584 ;
     RECT  3.336 21.516 3.408 21.584 ;
     RECT  3.432 21.516 3.504 21.584 ;
     RECT  3.528 21.516 3.6 21.584 ;
     RECT  3.624 21.516 3.696 21.584 ;
     RECT  3.72 21.516 3.792 21.584 ;
     RECT  3.816 21.516 3.888 21.584 ;
     RECT  3.912 21.516 3.984 21.584 ;
     RECT  4.008 21.516 4.08 21.584 ;
     RECT  4.104 21.516 4.176 21.584 ;
     RECT  4.2 21.516 4.272 21.584 ;
     RECT  4.296 21.516 4.368 21.584 ;
     RECT  4.392 21.516 4.464 21.584 ;
     RECT  4.488 21.516 4.56 21.584 ;
     RECT  4.584 21.516 4.656 21.584 ;
     RECT  4.68 21.516 4.752 21.584 ;
     RECT  4.776 21.516 4.848 21.584 ;
     RECT  4.872 21.516 4.944 21.584 ;
     RECT  4.968 21.516 5.04 21.584 ;
     RECT  5.064 21.516 5.136 21.584 ;
     RECT  5.16 21.516 5.232 21.584 ;
     RECT  5.256 21.516 5.328 21.584 ;
     RECT  5.352 21.516 5.424 21.584 ;
     RECT  5.448 21.516 5.52 21.584 ;
     RECT  5.544 21.516 5.616 21.584 ;
     RECT  5.64 21.516 5.712 21.584 ;
     RECT  5.736 21.516 5.808 21.584 ;
     RECT  5.832 21.516 5.904 21.584 ;
     RECT  5.928 21.516 6 21.584 ;
     RECT  6.024 21.516 6.096 21.584 ;
     RECT  6.12 21.516 6.192 21.584 ;
     RECT  6.216 21.516 6.288 21.584 ;
     RECT  6.312 21.516 6.384 21.584 ;
     RECT  6.408 21.516 6.48 21.584 ;
     RECT  6.504 21.516 6.576 21.584 ;
     RECT  6.6 21.516 6.672 21.584 ;
     RECT  6.696 21.516 6.768 21.584 ;
     RECT  6.792 21.516 6.864 21.584 ;
     RECT  6.888 21.516 6.96 21.584 ;
     RECT  6.984 21.516 7.056 21.584 ;
     RECT  7.08 21.516 7.152 21.584 ;
     RECT  7.176 21.516 7.248 21.584 ;
     RECT  7.272 21.516 7.344 21.584 ;
     RECT  7.368 21.516 7.44 21.584 ;
     RECT  7.464 21.516 7.536 21.584 ;
     RECT  7.56 21.516 7.632 21.584 ;
     RECT  7.656 21.516 7.728 21.584 ;
     RECT  7.752 21.516 7.824 21.584 ;
     RECT  7.848 21.516 7.92 21.584 ;
     RECT  7.944 21.516 8.016 21.584 ;
     RECT  8.04 21.516 8.112 21.584 ;
     RECT  8.136 21.516 8.208 21.584 ;
     RECT  8.232 21.516 8.304 21.584 ;
     RECT  8.328 21.516 8.4 21.584 ;
     RECT  8.424 21.516 8.496 21.584 ;
     RECT  8.52 21.516 8.592 21.584 ;
     RECT  8.616 21.516 8.688 21.584 ;
     RECT  8.712 21.516 8.784 21.584 ;
     RECT  8.808 21.516 8.88 21.584 ;
     RECT  8.904 21.516 8.976 21.584 ;
     RECT  9 21.516 9.072 21.584 ;
     RECT  9.096 21.516 9.168 21.584 ;
     RECT  9.192 21.516 9.264 21.584 ;
     RECT  9.288 21.516 9.36 21.584 ;
     RECT  9.384 21.516 9.456 21.584 ;
     RECT  9.48 21.516 9.552 21.584 ;
     RECT  9.576 21.516 9.648 21.584 ;
     RECT  9.672 21.516 9.744 21.584 ;
     RECT  9.768 21.516 9.84 21.584 ;
     RECT  9.864 21.516 9.936 21.584 ;
     RECT  9.96 21.516 10.032 21.584 ;
     RECT  10.056 21.516 10.128 21.584 ;
     RECT  10.152 21.516 10.224 21.584 ;
     RECT  10.248 21.516 10.32 21.584 ;
     RECT  10.344 21.516 10.416 21.584 ;
     RECT  10.44 21.516 10.512 21.584 ;
     RECT  10.536 21.516 10.608 21.584 ;
     RECT  10.632 21.516 10.704 21.584 ;
     RECT  10.728 21.516 10.8 21.584 ;
     RECT  10.824 21.516 10.896 21.584 ;
     RECT  10.92 21.516 10.992 21.584 ;
     RECT  11.016 21.516 11.088 21.584 ;
     RECT  11.112 21.516 11.184 21.584 ;
     RECT  11.208 21.516 11.28 21.584 ;
     RECT  11.304 21.516 11.376 21.584 ;
     RECT  11.4 21.516 11.472 21.584 ;
     RECT  11.496 21.516 11.568 21.584 ;
     RECT  11.592 21.516 11.664 21.584 ;
     RECT  11.688 21.516 11.76 21.584 ;
     RECT  11.784 21.516 11.856 21.584 ;
     RECT  11.88 21.516 11.952 21.584 ;
     RECT  11.976 21.516 12.048 21.584 ;
     RECT  12.072 21.516 12.144 21.584 ;
     RECT  12.168 21.516 12.24 21.584 ;
     RECT  12.264 21.516 12.336 21.584 ;
     RECT  12.36 21.516 12.432 21.584 ;
     RECT  12.456 21.516 12.528 21.584 ;
     RECT  12.552 21.516 12.624 21.584 ;
     RECT  12.648 21.516 12.72 21.584 ;
     RECT  12.744 21.516 12.816 21.584 ;
     RECT  12.84 21.516 12.912 21.584 ;
     RECT  12.936 21.516 13.008 21.584 ;
     RECT  13.032 21.516 13.104 21.584 ;
     RECT  13.128 21.516 13.2 21.584 ;
     RECT  13.224 21.516 13.296 21.584 ;
     RECT  13.32 21.516 13.392 21.584 ;
     RECT  13.416 21.516 13.488 21.584 ;
     RECT  13.512 21.516 13.584 21.584 ;
     RECT  13.608 21.516 13.68 21.584 ;
     RECT  13.704 21.516 13.776 21.584 ;
     RECT  13.8 21.516 13.872 21.584 ;
     RECT  13.896 21.516 13.968 21.584 ;
     RECT  13.992 21.516 14.064 21.584 ;
     RECT  14.088 21.516 14.16 21.584 ;
     RECT  14.184 21.516 14.256 21.584 ;
     RECT  14.28 21.516 14.352 21.584 ;
     RECT  14.376 21.516 14.448 21.584 ;
     RECT  14.472 21.516 14.544 21.584 ;
     RECT  14.568 21.516 14.64 21.584 ;
     RECT  17.04 19.463 17.736 21.516 ;
     RECT  17.064 21.516 17.136 21.584 ;
     RECT  17.16 21.516 17.232 21.584 ;
     RECT  17.256 21.516 17.328 21.584 ;
     RECT  17.352 21.516 17.424 21.584 ;
     RECT  17.448 21.516 17.52 21.584 ;
     RECT  17.544 21.516 17.616 21.584 ;
     RECT  17.64 21.516 17.712 21.584 ;
     RECT  6.864 1.187 6.96 1.235 ;
     RECT  6.864 1.235 7.056 2.151 ;
     RECT  5.412 2.151 7.056 2.533 ;
     RECT  10.812 6.323 12 6.371 ;
     RECT  11.592 10.117 12.96 10.165 ;
     RECT  12.12 10.979 13.2 12.469 ;
     RECT  2.712 12.325 3.936 13.045 ;
     RECT  3.96 12.325 5.1 13.045 ;
     RECT  2.904 13.045 3.936 14.291 ;
     RECT  17.448 14.867 18.6 16.115 ;
     RECT  18.912 14.963 20.016 16.835 ;
     RECT  13.8 15.443 15.024 15.827 ;
     RECT  16.212 15.587 17.424 16.115 ;
     RECT  13.8 15.827 14.232 16.837 ;
     RECT  16.212 16.115 16.536 16.885 ;
     RECT  18.912 16.835 20.064 17.123 ;
     RECT  13.896 16.837 14.232 16.933 ;
     RECT  13.944 16.933 14.232 17.029 ;
     RECT  2.904 17.029 3.936 18.181 ;
     RECT  18.912 17.123 20.256 17.651 ;
     RECT  16.212 17.939 16.536 18.997 ;
     RECT  15.792 18.179 15.9 19.237 ;
     RECT  16.212 18.997 17.616 19.285 ;
     RECT  14.28 19.237 15.9 19.285 ;
     RECT  14.664 19.285 15.9 19.463 ;
     RECT  16.02 19.449 17.04 19.463 ;
  END
END hbfd_rly_136_NS
END LIBRARY
